VERSION 5.7 ;
  NOWIREEXTENSIONATPIN ON ;
  DIVIDERCHAR "/" ;
  BUSBITCHARS "[]" ;
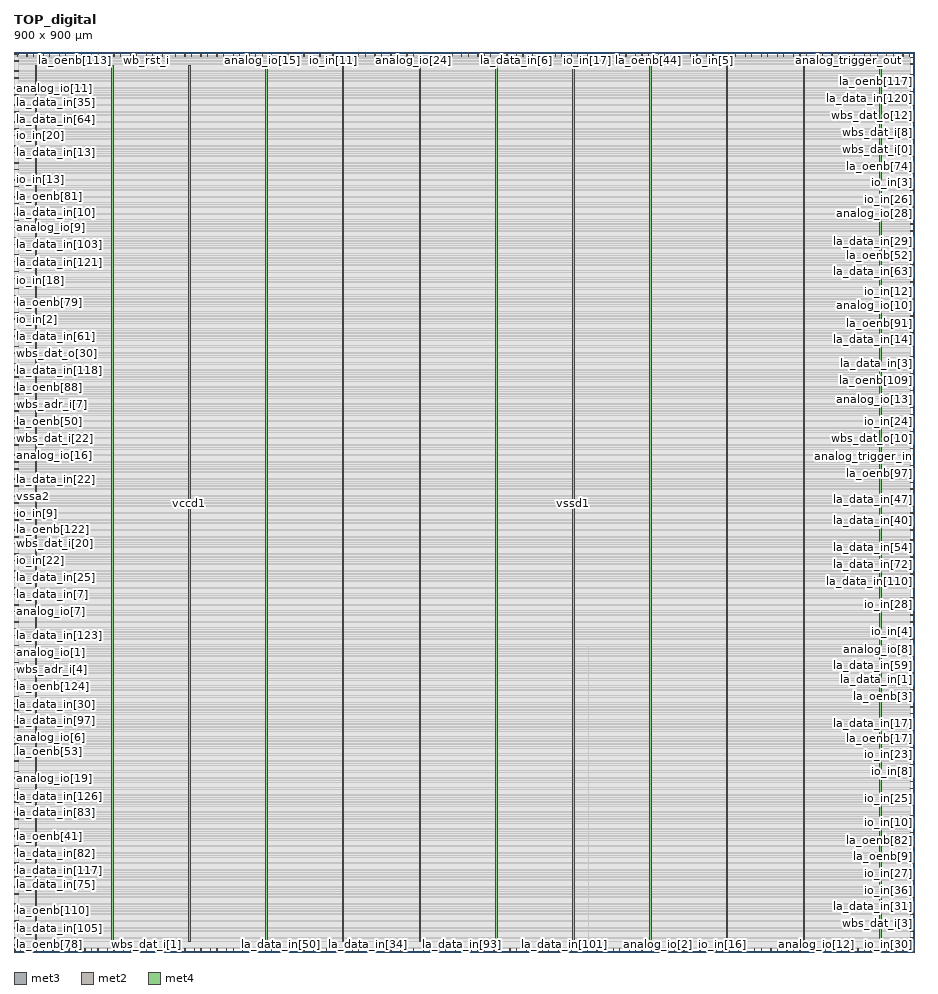
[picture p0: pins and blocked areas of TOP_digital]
MACRO TOP_digital
  CLASS BLOCK ;
  FOREIGN TOP_digital ;
  ORIGIN 0.000 0.000 ;
  SIZE 900.000 BY 900.000 ;
  PIN analog_io[0]
    DIRECTION INOUT ;
    USE SIGNAL ;
    PORT
      LAYER met3 ;
        RECT 0.000 639.240 4.000 639.840 ;
    END
  END analog_io[0]
  PIN analog_io[10]
    DIRECTION INOUT ;
    USE SIGNAL ;
    PORT
      LAYER met3 ;
        RECT 896.000 646.040 900.000 646.640 ;
    END
  END analog_io[10]
  PIN analog_io[11]
    DIRECTION INOUT ;
    USE SIGNAL ;
    PORT
      LAYER met3 ;
        RECT 0.000 863.640 4.000 864.240 ;
    END
  END analog_io[11]
  PIN analog_io[12]
    DIRECTION INOUT ;
    USE SIGNAL ;
    PORT
      LAYER met2 ;
        RECT 801.870 0.000 802.150 4.000 ;
    END
  END analog_io[12]
  PIN analog_io[13]
    DIRECTION INOUT ;
    USE SIGNAL ;
    PORT
      LAYER met3 ;
        RECT 896.000 544.040 900.000 544.640 ;
    END
  END analog_io[13]
  PIN analog_io[14]
    DIRECTION INOUT ;
    USE SIGNAL ;
    PORT
      LAYER met3 ;
        RECT 896.000 877.240 900.000 877.840 ;
    END
  END analog_io[14]
  PIN analog_io[15]
    DIRECTION INOUT ;
    USE SIGNAL ;
    PORT
      LAYER met2 ;
        RECT 248.030 896.000 248.310 900.000 ;
    END
  END analog_io[15]
  PIN analog_io[16]
    DIRECTION INOUT ;
    USE SIGNAL ;
    PORT
      LAYER met3 ;
        RECT 0.000 496.440 4.000 497.040 ;
    END
  END analog_io[16]
  PIN analog_io[17]
    DIRECTION INOUT ;
    USE SIGNAL ;
    PORT
      LAYER met2 ;
        RECT 106.350 896.000 106.630 900.000 ;
    END
  END analog_io[17]
  PIN analog_io[18]
    DIRECTION INOUT ;
    USE SIGNAL ;
    PORT
      LAYER met2 ;
        RECT 67.710 896.000 67.990 900.000 ;
    END
  END analog_io[18]
  PIN analog_io[19]
    DIRECTION INOUT ;
    USE SIGNAL ;
    PORT
      LAYER met3 ;
        RECT 0.000 173.440 4.000 174.040 ;
    END
  END analog_io[19]
  PIN analog_io[1]
    DIRECTION INOUT ;
    USE SIGNAL ;
    PORT
      LAYER met3 ;
        RECT 0.000 299.240 4.000 299.840 ;
    END
  END analog_io[1]
  PIN analog_io[20]
    DIRECTION INOUT ;
    USE SIGNAL ;
    PORT
      LAYER met3 ;
        RECT 0.000 363.840 4.000 364.440 ;
    END
  END analog_io[20]
  PIN analog_io[21]
    DIRECTION INOUT ;
    USE SIGNAL ;
    PORT
      LAYER met2 ;
        RECT 621.550 896.000 621.830 900.000 ;
    END
  END analog_io[21]
  PIN analog_io[22]
    DIRECTION INOUT ;
    USE SIGNAL ;
    PORT
      LAYER met2 ;
        RECT 77.370 896.000 77.650 900.000 ;
    END
  END analog_io[22]
  PIN analog_io[23]
    DIRECTION INOUT ;
    USE SIGNAL ;
    PORT
      LAYER met2 ;
        RECT 785.770 0.000 786.050 4.000 ;
    END
  END analog_io[23]
  PIN analog_io[24]
    DIRECTION INOUT ;
    USE SIGNAL ;
    PORT
      LAYER met2 ;
        RECT 399.370 896.000 399.650 900.000 ;
    END
  END analog_io[24]
  PIN analog_io[25]
    DIRECTION INOUT ;
    USE SIGNAL ;
    PORT
      LAYER met3 ;
        RECT 0.000 880.640 4.000 881.240 ;
    END
  END analog_io[25]
  PIN analog_io[26]
    DIRECTION INOUT ;
    USE SIGNAL ;
    PORT
      LAYER met2 ;
        RECT 714.930 896.000 715.210 900.000 ;
    END
  END analog_io[26]
  PIN analog_io[27]
    DIRECTION INOUT ;
    USE SIGNAL ;
    PORT
      LAYER met3 ;
        RECT 0.000 47.640 4.000 48.240 ;
    END
  END analog_io[27]
  PIN analog_io[28]
    DIRECTION INOUT ;
    USE SIGNAL ;
    PORT
      LAYER met3 ;
        RECT 896.000 737.840 900.000 738.440 ;
    END
  END analog_io[28]
  PIN analog_io[2]
    DIRECTION INOUT ;
    USE SIGNAL ;
    PORT
      LAYER met2 ;
        RECT 644.090 0.000 644.370 4.000 ;
    END
  END analog_io[2]
  PIN analog_io[3]
    DIRECTION INOUT ;
    USE SIGNAL ;
    PORT
      LAYER met2 ;
        RECT 431.570 0.000 431.850 4.000 ;
    END
  END analog_io[3]
  PIN analog_io[4]
    DIRECTION INOUT ;
    USE SIGNAL ;
    PORT
      LAYER met2 ;
        RECT 476.650 896.000 476.930 900.000 ;
    END
  END analog_io[4]
  PIN analog_io[5]
    DIRECTION INOUT ;
    USE SIGNAL ;
    PORT
      LAYER met2 ;
        RECT 99.910 0.000 100.190 4.000 ;
    END
  END analog_io[5]
  PIN analog_io[6]
    DIRECTION INOUT ;
    USE SIGNAL ;
    PORT
      LAYER met3 ;
        RECT 0.000 214.240 4.000 214.840 ;
    END
  END analog_io[6]
  PIN analog_io[7]
    DIRECTION INOUT ;
    USE SIGNAL ;
    PORT
      LAYER met3 ;
        RECT 0.000 340.040 4.000 340.640 ;
    END
  END analog_io[7]
  PIN analog_io[8]
    DIRECTION INOUT ;
    USE SIGNAL ;
    PORT
      LAYER met3 ;
        RECT 896.000 302.640 900.000 303.240 ;
    END
  END analog_io[8]
  PIN analog_io[9]
    DIRECTION INOUT ;
    USE SIGNAL ;
    PORT
      LAYER met3 ;
        RECT 0.000 724.240 4.000 724.840 ;
    END
  END analog_io[9]
  PIN analog_trigger_in
    DIRECTION INOUT ;
    USE SIGNAL ;
    PORT
      LAYER met3 ;
        RECT 896.000 503.240 900.000 503.840 ;
    END
  END analog_trigger_in
  PIN analog_trigger_out
    DIRECTION INOUT ;
    USE SIGNAL ;
    PORT
      LAYER met2 ;
        RECT 834.070 896.000 834.350 900.000 ;
    END
  END analog_trigger_out
  PIN io_in[0]
    DIRECTION INPUT ;
    USE SIGNAL ;
    PORT
      LAYER met3 ;
        RECT 896.000 105.440 900.000 106.040 ;
    END
  END io_in[0]
  PIN io_in[10]
    DIRECTION INPUT ;
    USE SIGNAL ;
    PORT
      LAYER met3 ;
        RECT 896.000 129.240 900.000 129.840 ;
    END
  END io_in[10]
  PIN io_in[11]
    DIRECTION INPUT ;
    USE SIGNAL ;
    PORT
      LAYER met2 ;
        RECT 318.870 896.000 319.150 900.000 ;
    END
  END io_in[11]
  PIN io_in[12]
    DIRECTION INPUT ;
    USE SIGNAL ;
    PORT
      LAYER met3 ;
        RECT 896.000 652.840 900.000 653.440 ;
    END
  END io_in[12]
  PIN io_in[13]
    DIRECTION INPUT ;
    USE SIGNAL ;
    PORT
      LAYER met3 ;
        RECT 0.000 771.840 4.000 772.440 ;
    END
  END io_in[13]
  PIN io_in[14]
    DIRECTION INPUT ;
    USE SIGNAL ;
    PORT
      LAYER met2 ;
        RECT 772.890 0.000 773.170 4.000 ;
    END
  END io_in[14]
  PIN io_in[15]
    DIRECTION INPUT ;
    USE SIGNAL ;
    PORT
      LAYER met3 ;
        RECT 0.000 105.440 4.000 106.040 ;
    END
  END io_in[15]
  PIN io_in[16]
    DIRECTION INPUT ;
    USE SIGNAL ;
    PORT
      LAYER met2 ;
        RECT 708.490 0.000 708.770 4.000 ;
    END
  END io_in[16]
  PIN io_in[17]
    DIRECTION INPUT ;
    USE SIGNAL ;
    PORT
      LAYER met2 ;
        RECT 573.250 896.000 573.530 900.000 ;
    END
  END io_in[17]
  PIN io_in[18]
    DIRECTION INPUT ;
    USE SIGNAL ;
    PORT
      LAYER met3 ;
        RECT 0.000 663.040 4.000 663.640 ;
    END
  END io_in[18]
  PIN io_in[19]
    DIRECTION INPUT ;
    USE SIGNAL ;
    PORT
      LAYER met2 ;
        RECT 817.970 0.000 818.250 4.000 ;
    END
  END io_in[19]
  PIN io_in[1]
    DIRECTION INPUT ;
    USE SIGNAL ;
    PORT
      LAYER met2 ;
        RECT 22.630 0.000 22.910 4.000 ;
    END
  END io_in[1]
  PIN io_in[20]
    DIRECTION INPUT ;
    USE SIGNAL ;
    PORT
      LAYER met3 ;
        RECT 0.000 816.040 4.000 816.640 ;
    END
  END io_in[20]
  PIN io_in[21]
    DIRECTION INPUT ;
    USE SIGNAL ;
    PORT
      LAYER met2 ;
        RECT 660.190 0.000 660.470 4.000 ;
    END
  END io_in[21]
  PIN io_in[22]
    DIRECTION INPUT ;
    USE SIGNAL ;
    PORT
      LAYER met3 ;
        RECT 0.000 391.040 4.000 391.640 ;
    END
  END io_in[22]
  PIN io_in[23]
    DIRECTION INPUT ;
    USE SIGNAL ;
    PORT
      LAYER met3 ;
        RECT 896.000 197.240 900.000 197.840 ;
    END
  END io_in[23]
  PIN io_in[24]
    DIRECTION INPUT ;
    USE SIGNAL ;
    PORT
      LAYER met3 ;
        RECT 896.000 530.440 900.000 531.040 ;
    END
  END io_in[24]
  PIN io_in[25]
    DIRECTION INPUT ;
    USE SIGNAL ;
    PORT
      LAYER met3 ;
        RECT 896.000 153.040 900.000 153.640 ;
    END
  END io_in[25]
  PIN io_in[26]
    DIRECTION INPUT ;
    USE SIGNAL ;
    PORT
      LAYER met3 ;
        RECT 896.000 744.640 900.000 745.240 ;
    END
  END io_in[26]
  PIN io_in[27]
    DIRECTION INPUT ;
    USE SIGNAL ;
    PORT
      LAYER met3 ;
        RECT 896.000 78.240 900.000 78.840 ;
    END
  END io_in[27]
  PIN io_in[28]
    DIRECTION INPUT ;
    USE SIGNAL ;
    PORT
      LAYER met3 ;
        RECT 896.000 346.840 900.000 347.440 ;
    END
  END io_in[28]
  PIN io_in[29]
    DIRECTION INPUT ;
    USE SIGNAL ;
    PORT
      LAYER met2 ;
        RECT 122.450 896.000 122.730 900.000 ;
    END
  END io_in[29]
  PIN io_in[2]
    DIRECTION INPUT ;
    USE SIGNAL ;
    PORT
      LAYER met3 ;
        RECT 0.000 632.440 4.000 633.040 ;
    END
  END io_in[2]
  PIN io_in[30]
    DIRECTION INPUT ;
    USE SIGNAL ;
    PORT
      LAYER met2 ;
        RECT 898.470 0.000 898.750 4.000 ;
    END
  END io_in[30]
  PIN io_in[31]
    DIRECTION INPUT ;
    USE SIGNAL ;
    PORT
      LAYER met2 ;
        RECT 116.010 0.000 116.290 4.000 ;
    END
  END io_in[31]
  PIN io_in[32]
    DIRECTION INPUT ;
    USE SIGNAL ;
    PORT
      LAYER met2 ;
        RECT 29.070 896.000 29.350 900.000 ;
    END
  END io_in[32]
  PIN io_in[33]
    DIRECTION INPUT ;
    USE SIGNAL ;
    PORT
      LAYER met3 ;
        RECT 896.000 13.640 900.000 14.240 ;
    END
  END io_in[33]
  PIN io_in[34]
    DIRECTION INPUT ;
    USE SIGNAL ;
    PORT
      LAYER met2 ;
        RECT 289.890 0.000 290.170 4.000 ;
    END
  END io_in[34]
  PIN io_in[35]
    DIRECTION INPUT ;
    USE SIGNAL ;
    PORT
      LAYER met2 ;
        RECT 856.610 896.000 856.890 900.000 ;
    END
  END io_in[35]
  PIN io_in[36]
    DIRECTION INPUT ;
    USE SIGNAL ;
    PORT
      LAYER met3 ;
        RECT 896.000 61.240 900.000 61.840 ;
    END
  END io_in[36]
  PIN io_in[37]
    DIRECTION INPUT ;
    USE SIGNAL ;
    PORT
      LAYER met3 ;
        RECT 0.000 329.840 4.000 330.440 ;
    END
  END io_in[37]
  PIN io_in[3]
    DIRECTION INPUT ;
    USE SIGNAL ;
    PORT
      LAYER met3 ;
        RECT 896.000 761.640 900.000 762.240 ;
    END
  END io_in[3]
  PIN io_in[4]
    DIRECTION INPUT ;
    USE SIGNAL ;
    PORT
      LAYER met3 ;
        RECT 896.000 312.840 900.000 313.440 ;
    END
  END io_in[4]
  PIN io_in[5]
    DIRECTION INPUT ;
    USE SIGNAL ;
    PORT
      LAYER met2 ;
        RECT 698.830 896.000 699.110 900.000 ;
    END
  END io_in[5]
  PIN io_in[6]
    DIRECTION INPUT ;
    USE SIGNAL ;
    PORT
      LAYER met2 ;
        RECT 888.810 896.000 889.090 900.000 ;
    END
  END io_in[6]
  PIN io_in[7]
    DIRECTION INPUT ;
    USE SIGNAL ;
    PORT
      LAYER met2 ;
        RECT 740.690 0.000 740.970 4.000 ;
    END
  END io_in[7]
  PIN io_in[8]
    DIRECTION INPUT ;
    USE SIGNAL ;
    PORT
      LAYER met3 ;
        RECT 896.000 180.240 900.000 180.840 ;
    END
  END io_in[8]
  PIN io_in[9]
    DIRECTION INPUT ;
    USE SIGNAL ;
    PORT
      LAYER met3 ;
        RECT 0.000 438.640 4.000 439.240 ;
    END
  END io_in[9]
  PIN la_data_in[0]
    DIRECTION INPUT ;
    USE SIGNAL ;
    ANTENNAGATEAREA 0.495000 ;
    PORT
      LAYER met3 ;
        RECT 0.000 132.640 4.000 133.240 ;
    END
  END la_data_in[0]
  PIN la_data_in[100]
    DIRECTION INPUT ;
    USE SIGNAL ;
    PORT
      LAYER met2 ;
        RECT 328.530 896.000 328.810 900.000 ;
    END
  END la_data_in[100]
  PIN la_data_in[101]
    DIRECTION INPUT ;
    USE SIGNAL ;
    PORT
      LAYER met2 ;
        RECT 550.710 0.000 550.990 4.000 ;
    END
  END la_data_in[101]
  PIN la_data_in[102]
    DIRECTION INPUT ;
    USE SIGNAL ;
    PORT
      LAYER met2 ;
        RECT 312.430 896.000 312.710 900.000 ;
    END
  END la_data_in[102]
  PIN la_data_in[103]
    DIRECTION INPUT ;
    USE SIGNAL ;
    PORT
      LAYER met3 ;
        RECT 0.000 707.240 4.000 707.840 ;
    END
  END la_data_in[103]
  PIN la_data_in[104]
    DIRECTION INPUT ;
    USE SIGNAL ;
    PORT
      LAYER met2 ;
        RECT 415.470 896.000 415.750 900.000 ;
    END
  END la_data_in[104]
  PIN la_data_in[105]
    DIRECTION INPUT ;
    USE SIGNAL ;
    PORT
      LAYER met3 ;
        RECT 0.000 30.640 4.000 31.240 ;
    END
  END la_data_in[105]
  PIN la_data_in[106]
    DIRECTION INPUT ;
    USE SIGNAL ;
    PORT
      LAYER met2 ;
        RECT 148.210 0.000 148.490 4.000 ;
    END
  END la_data_in[106]
  PIN la_data_in[107]
    DIRECTION INPUT ;
    USE SIGNAL ;
    PORT
      LAYER met2 ;
        RECT 425.130 0.000 425.410 4.000 ;
    END
  END la_data_in[107]
  PIN la_data_in[108]
    DIRECTION INPUT ;
    USE SIGNAL ;
    PORT
      LAYER met2 ;
        RECT 544.270 0.000 544.550 4.000 ;
    END
  END la_data_in[108]
  PIN la_data_in[109]
    DIRECTION INPUT ;
    USE SIGNAL ;
    PORT
      LAYER met3 ;
        RECT 896.000 520.240 900.000 520.840 ;
    END
  END la_data_in[109]
  PIN la_data_in[10]
    DIRECTION INPUT ;
    USE SIGNAL ;
    PORT
      LAYER met3 ;
        RECT 0.000 731.040 4.000 731.640 ;
    END
  END la_data_in[10]
  PIN la_data_in[110]
    DIRECTION INPUT ;
    USE SIGNAL ;
    PORT
      LAYER met3 ;
        RECT 896.000 370.640 900.000 371.240 ;
    END
  END la_data_in[110]
  PIN la_data_in[111]
    DIRECTION INPUT ;
    USE SIGNAL ;
    PORT
      LAYER met3 ;
        RECT 896.000 812.640 900.000 813.240 ;
    END
  END la_data_in[111]
  PIN la_data_in[112]
    DIRECTION INPUT ;
    USE SIGNAL ;
    PORT
      LAYER met3 ;
        RECT 896.000 846.640 900.000 847.240 ;
    END
  END la_data_in[112]
  PIN la_data_in[113]
    DIRECTION INPUT ;
    USE SIGNAL ;
    PORT
      LAYER met2 ;
        RECT 219.050 0.000 219.330 4.000 ;
    END
  END la_data_in[113]
  PIN la_data_in[114]
    DIRECTION INPUT ;
    USE SIGNAL ;
    PORT
      LAYER met3 ;
        RECT 896.000 71.440 900.000 72.040 ;
    END
  END la_data_in[114]
  PIN la_data_in[115]
    DIRECTION INPUT ;
    USE SIGNAL ;
    PORT
      LAYER met2 ;
        RECT 83.810 0.000 84.090 4.000 ;
    END
  END la_data_in[115]
  PIN la_data_in[116]
    DIRECTION INPUT ;
    USE SIGNAL ;
    PORT
      LAYER met2 ;
        RECT 573.250 0.000 573.530 4.000 ;
    END
  END la_data_in[116]
  PIN la_data_in[117]
    DIRECTION INPUT ;
    USE SIGNAL ;
    PORT
      LAYER met3 ;
        RECT 0.000 81.640 4.000 82.240 ;
    END
  END la_data_in[117]
  PIN la_data_in[118]
    DIRECTION INPUT ;
    USE SIGNAL ;
    PORT
      LAYER met3 ;
        RECT 0.000 581.440 4.000 582.040 ;
    END
  END la_data_in[118]
  PIN la_data_in[119]
    DIRECTION INPUT ;
    USE SIGNAL ;
    PORT
      LAYER met2 ;
        RECT 405.810 896.000 406.090 900.000 ;
    END
  END la_data_in[119]
  PIN la_data_in[11]
    DIRECTION INPUT ;
    USE SIGNAL ;
    PORT
      LAYER met3 ;
        RECT 0.000 656.240 4.000 656.840 ;
    END
  END la_data_in[11]
  PIN la_data_in[120]
    DIRECTION INPUT ;
    USE SIGNAL ;
    PORT
      LAYER met3 ;
        RECT 896.000 853.440 900.000 854.040 ;
    END
  END la_data_in[120]
  PIN la_data_in[121]
    DIRECTION INPUT ;
    USE SIGNAL ;
    PORT
      LAYER met3 ;
        RECT 0.000 697.040 4.000 697.640 ;
    END
  END la_data_in[121]
  PIN la_data_in[122]
    DIRECTION INPUT ;
    USE SIGNAL ;
    PORT
      LAYER met2 ;
        RECT 125.670 0.000 125.950 4.000 ;
    END
  END la_data_in[122]
  PIN la_data_in[123]
    DIRECTION INPUT ;
    USE SIGNAL ;
    PORT
      LAYER met3 ;
        RECT 0.000 316.240 4.000 316.840 ;
    END
  END la_data_in[123]
  PIN la_data_in[124]
    DIRECTION INPUT ;
    USE SIGNAL ;
    PORT
      LAYER met3 ;
        RECT 0.000 557.640 4.000 558.240 ;
    END
  END la_data_in[124]
  PIN la_data_in[125]
    DIRECTION INPUT ;
    USE SIGNAL ;
    PORT
      LAYER met2 ;
        RECT 827.630 0.000 827.910 4.000 ;
    END
  END la_data_in[125]
  PIN la_data_in[126]
    DIRECTION INPUT ;
    USE SIGNAL ;
    PORT
      LAYER met3 ;
        RECT 0.000 163.240 4.000 163.840 ;
    END
  END la_data_in[126]
  PIN la_data_in[127]
    DIRECTION INPUT ;
    USE SIGNAL ;
    PORT
      LAYER met2 ;
        RECT 518.510 896.000 518.790 900.000 ;
    END
  END la_data_in[127]
  PIN la_data_in[12]
    DIRECTION INPUT ;
    USE SIGNAL ;
    PORT
      LAYER met2 ;
        RECT 219.050 896.000 219.330 900.000 ;
    END
  END la_data_in[12]
  PIN la_data_in[13]
    DIRECTION INPUT ;
    USE SIGNAL ;
    PORT
      LAYER met3 ;
        RECT 0.000 799.040 4.000 799.640 ;
    END
  END la_data_in[13]
  PIN la_data_in[14]
    DIRECTION INPUT ;
    USE SIGNAL ;
    PORT
      LAYER met3 ;
        RECT 896.000 612.040 900.000 612.640 ;
    END
  END la_data_in[14]
  PIN la_data_in[15]
    DIRECTION INPUT ;
    USE SIGNAL ;
    PORT
      LAYER met2 ;
        RECT 792.210 896.000 792.490 900.000 ;
    END
  END la_data_in[15]
  PIN la_data_in[16]
    DIRECTION INPUT ;
    USE SIGNAL ;
    PORT
      LAYER met2 ;
        RECT 3.310 896.000 3.590 900.000 ;
    END
  END la_data_in[16]
  PIN la_data_in[17]
    DIRECTION INPUT ;
    USE SIGNAL ;
    PORT
      LAYER met3 ;
        RECT 896.000 227.840 900.000 228.440 ;
    END
  END la_data_in[17]
  PIN la_data_in[18]
    DIRECTION INPUT ;
    USE SIGNAL ;
    PORT
      LAYER met3 ;
        RECT 0.000 323.040 4.000 323.640 ;
    END
  END la_data_in[18]
  PIN la_data_in[19]
    DIRECTION INPUT ;
    USE SIGNAL ;
    PORT
      LAYER met2 ;
        RECT 421.910 896.000 422.190 900.000 ;
    END
  END la_data_in[19]
  PIN la_data_in[1]
    DIRECTION INPUT ;
    USE SIGNAL ;
    PORT
      LAYER met3 ;
        RECT 896.000 272.040 900.000 272.640 ;
    END
  END la_data_in[1]
  PIN la_data_in[20]
    DIRECTION INPUT ;
    USE SIGNAL ;
    PORT
      LAYER met2 ;
        RECT 177.190 896.000 177.470 900.000 ;
    END
  END la_data_in[20]
  PIN la_data_in[21]
    DIRECTION INPUT ;
    USE SIGNAL ;
    PORT
      LAYER met3 ;
        RECT 896.000 210.840 900.000 211.440 ;
    END
  END la_data_in[21]
  PIN la_data_in[22]
    DIRECTION INPUT ;
    USE SIGNAL ;
    PORT
      LAYER met3 ;
        RECT 0.000 472.640 4.000 473.240 ;
    END
  END la_data_in[22]
  PIN la_data_in[23]
    DIRECTION INPUT ;
    USE SIGNAL ;
    PORT
      LAYER met3 ;
        RECT 0.000 622.240 4.000 622.840 ;
    END
  END la_data_in[23]
  PIN la_data_in[24]
    DIRECTION INPUT ;
    USE SIGNAL ;
    PORT
      LAYER met2 ;
        RECT 872.710 896.000 872.990 900.000 ;
    END
  END la_data_in[24]
  PIN la_data_in[25]
    DIRECTION INPUT ;
    USE SIGNAL ;
    PORT
      LAYER met3 ;
        RECT 0.000 374.040 4.000 374.640 ;
    END
  END la_data_in[25]
  PIN la_data_in[26]
    DIRECTION INPUT ;
    USE SIGNAL ;
    PORT
      LAYER met2 ;
        RECT 508.850 896.000 509.130 900.000 ;
    END
  END la_data_in[26]
  PIN la_data_in[27]
    DIRECTION INPUT ;
    USE SIGNAL ;
    PORT
      LAYER met3 ;
        RECT 0.000 122.440 4.000 123.040 ;
    END
  END la_data_in[27]
  PIN la_data_in[28]
    DIRECTION INPUT ;
    USE SIGNAL ;
    PORT
      LAYER met3 ;
        RECT 0.000 506.640 4.000 507.240 ;
    END
  END la_data_in[28]
  PIN la_data_in[29]
    DIRECTION INPUT ;
    USE SIGNAL ;
    PORT
      LAYER met3 ;
        RECT 896.000 710.640 900.000 711.240 ;
    END
  END la_data_in[29]
  PIN la_data_in[2]
    DIRECTION INPUT ;
    USE SIGNAL ;
    PORT
      LAYER met3 ;
        RECT 0.000 805.840 4.000 806.440 ;
    END
  END la_data_in[2]
  PIN la_data_in[30]
    DIRECTION INPUT ;
    USE SIGNAL ;
    PORT
      LAYER met3 ;
        RECT 0.000 255.040 4.000 255.640 ;
    END
  END la_data_in[30]
  PIN la_data_in[31]
    DIRECTION INPUT ;
    USE SIGNAL ;
    PORT
      LAYER met3 ;
        RECT 896.000 37.440 900.000 38.040 ;
    END
  END la_data_in[31]
  PIN la_data_in[32]
    DIRECTION INPUT ;
    USE SIGNAL ;
    PORT
      LAYER met2 ;
        RECT 90.250 896.000 90.530 900.000 ;
    END
  END la_data_in[32]
  PIN la_data_in[33]
    DIRECTION INPUT ;
    USE SIGNAL ;
    PORT
      LAYER met2 ;
        RECT 808.310 896.000 808.590 900.000 ;
    END
  END la_data_in[33]
  PIN la_data_in[34]
    DIRECTION INPUT ;
    USE SIGNAL ;
    PORT
      LAYER met2 ;
        RECT 354.290 0.000 354.570 4.000 ;
    END
  END la_data_in[34]
  PIN la_data_in[35]
    DIRECTION INPUT ;
    USE SIGNAL ;
    PORT
      LAYER met3 ;
        RECT 0.000 856.840 4.000 857.440 ;
    END
  END la_data_in[35]
  PIN la_data_in[36]
    DIRECTION INPUT ;
    USE SIGNAL ;
    PORT
      LAYER met2 ;
        RECT 447.670 896.000 447.950 900.000 ;
    END
  END la_data_in[36]
  PIN la_data_in[37]
    DIRECTION INPUT ;
    USE SIGNAL ;
    PORT
      LAYER met3 ;
        RECT 896.000 112.240 900.000 112.840 ;
    END
  END la_data_in[37]
  PIN la_data_in[38]
    DIRECTION INPUT ;
    USE SIGNAL ;
    PORT
      LAYER met2 ;
        RECT 863.050 896.000 863.330 900.000 ;
    END
  END la_data_in[38]
  PIN la_data_in[39]
    DIRECTION INPUT ;
    USE SIGNAL ;
    PORT
      LAYER met2 ;
        RECT 676.290 896.000 676.570 900.000 ;
    END
  END la_data_in[39]
  PIN la_data_in[3]
    DIRECTION INPUT ;
    USE SIGNAL ;
    PORT
      LAYER met3 ;
        RECT 896.000 588.240 900.000 588.840 ;
    END
  END la_data_in[3]
  PIN la_data_in[40]
    DIRECTION INPUT ;
    USE SIGNAL ;
    PORT
      LAYER met3 ;
        RECT 896.000 438.640 900.000 439.240 ;
    END
  END la_data_in[40]
  PIN la_data_in[41]
    DIRECTION INPUT ;
    USE SIGNAL ;
    PORT
      LAYER met2 ;
        RECT 524.950 896.000 525.230 900.000 ;
    END
  END la_data_in[41]
  PIN la_data_in[42]
    DIRECTION INPUT ;
    USE SIGNAL ;
    PORT
      LAYER met2 ;
        RECT 621.550 0.000 621.830 4.000 ;
    END
  END la_data_in[42]
  PIN la_data_in[43]
    DIRECTION INPUT ;
    USE SIGNAL ;
    PORT
      LAYER met3 ;
        RECT 0.000 23.840 4.000 24.440 ;
    END
  END la_data_in[43]
  PIN la_data_in[44]
    DIRECTION INPUT ;
    USE SIGNAL ;
    PORT
      LAYER met3 ;
        RECT 0.000 13.640 4.000 14.240 ;
    END
  END la_data_in[44]
  PIN la_data_in[45]
    DIRECTION INPUT ;
    USE SIGNAL ;
    PORT
      LAYER met2 ;
        RECT 351.070 896.000 351.350 900.000 ;
    END
  END la_data_in[45]
  PIN la_data_in[46]
    DIRECTION INPUT ;
    USE SIGNAL ;
    PORT
      LAYER met3 ;
        RECT 0.000 782.040 4.000 782.640 ;
    END
  END la_data_in[46]
  PIN la_data_in[47]
    DIRECTION INPUT ;
    USE SIGNAL ;
    PORT
      LAYER met3 ;
        RECT 896.000 452.240 900.000 452.840 ;
    END
  END la_data_in[47]
  PIN la_data_in[48]
    DIRECTION INPUT ;
    USE SIGNAL ;
    PORT
      LAYER met2 ;
        RECT 534.610 896.000 534.890 900.000 ;
    END
  END la_data_in[48]
  PIN la_data_in[49]
    DIRECTION INPUT ;
    USE SIGNAL ;
    PORT
      LAYER met2 ;
        RECT 154.650 0.000 154.930 4.000 ;
    END
  END la_data_in[49]
  PIN la_data_in[4]
    DIRECTION INPUT ;
    USE SIGNAL ;
    PORT
      LAYER met2 ;
        RECT 756.790 0.000 757.070 4.000 ;
    END
  END la_data_in[4]
  PIN la_data_in[50]
    DIRECTION INPUT ;
    USE SIGNAL ;
    PORT
      LAYER met2 ;
        RECT 267.350 0.000 267.630 4.000 ;
    END
  END la_data_in[50]
  PIN la_data_in[51]
    DIRECTION INPUT ;
    USE SIGNAL ;
    PORT
      LAYER met2 ;
        RECT 714.930 0.000 715.210 4.000 ;
    END
  END la_data_in[51]
  PIN la_data_in[52]
    DIRECTION INPUT ;
    USE SIGNAL ;
    PORT
      LAYER met3 ;
        RECT 896.000 136.040 900.000 136.640 ;
    END
  END la_data_in[52]
  PIN la_data_in[53]
    DIRECTION INPUT ;
    USE SIGNAL ;
    PORT
      LAYER met2 ;
        RECT 392.930 0.000 393.210 4.000 ;
    END
  END la_data_in[53]
  PIN la_data_in[54]
    DIRECTION INPUT ;
    USE SIGNAL ;
    PORT
      LAYER met3 ;
        RECT 896.000 404.640 900.000 405.240 ;
    END
  END la_data_in[54]
  PIN la_data_in[55]
    DIRECTION INPUT ;
    USE SIGNAL ;
    PORT
      LAYER met2 ;
        RECT 296.330 896.000 296.610 900.000 ;
    END
  END la_data_in[55]
  PIN la_data_in[56]
    DIRECTION INPUT ;
    USE SIGNAL ;
    PORT
      LAYER met2 ;
        RECT 12.970 896.000 13.250 900.000 ;
    END
  END la_data_in[56]
  PIN la_data_in[57]
    DIRECTION INPUT ;
    USE SIGNAL ;
    PORT
      LAYER met3 ;
        RECT 896.000 445.440 900.000 446.040 ;
    END
  END la_data_in[57]
  PIN la_data_in[58]
    DIRECTION INPUT ;
    USE SIGNAL ;
    PORT
      LAYER met2 ;
        RECT 763.230 896.000 763.510 900.000 ;
    END
  END la_data_in[58]
  PIN la_data_in[59]
    DIRECTION INPUT ;
    USE SIGNAL ;
    PORT
      LAYER met3 ;
        RECT 896.000 278.840 900.000 279.440 ;
    END
  END la_data_in[59]
  PIN la_data_in[5]
    DIRECTION INPUT ;
    USE SIGNAL ;
    PORT
      LAYER met2 ;
        RECT 731.030 0.000 731.310 4.000 ;
    END
  END la_data_in[5]
  PIN la_data_in[60]
    DIRECTION INPUT ;
    USE SIGNAL ;
    PORT
      LAYER met2 ;
        RECT 305.990 896.000 306.270 900.000 ;
    END
  END la_data_in[60]
  PIN la_data_in[61]
    DIRECTION INPUT ;
    USE SIGNAL ;
    PORT
      LAYER met3 ;
        RECT 0.000 615.440 4.000 616.040 ;
    END
  END la_data_in[61]
  PIN la_data_in[62]
    DIRECTION INPUT ;
    USE SIGNAL ;
    PORT
      LAYER met2 ;
        RECT 895.250 896.000 895.530 900.000 ;
    END
  END la_data_in[62]
  PIN la_data_in[63]
    DIRECTION INPUT ;
    USE SIGNAL ;
    PORT
      LAYER met3 ;
        RECT 896.000 680.040 900.000 680.640 ;
    END
  END la_data_in[63]
  PIN la_data_in[64]
    DIRECTION INPUT ;
    USE SIGNAL ;
    PORT
      LAYER met3 ;
        RECT 0.000 839.840 4.000 840.440 ;
    END
  END la_data_in[64]
  PIN la_data_in[65]
    DIRECTION INPUT ;
    USE SIGNAL ;
    PORT
      LAYER met2 ;
        RECT 370.390 0.000 370.670 4.000 ;
    END
  END la_data_in[65]
  PIN la_data_in[66]
    DIRECTION INPUT ;
    USE SIGNAL ;
    PORT
      LAYER met2 ;
        RECT 148.210 896.000 148.490 900.000 ;
    END
  END la_data_in[66]
  PIN la_data_in[67]
    DIRECTION INPUT ;
    USE SIGNAL ;
    PORT
      LAYER met2 ;
        RECT 627.990 0.000 628.270 4.000 ;
    END
  END la_data_in[67]
  PIN la_data_in[68]
    DIRECTION INPUT ;
    USE SIGNAL ;
    PORT
      LAYER met2 ;
        RECT 882.370 0.000 882.650 4.000 ;
    END
  END la_data_in[68]
  PIN la_data_in[69]
    DIRECTION INPUT ;
    USE SIGNAL ;
    PORT
      LAYER met2 ;
        RECT 322.090 0.000 322.370 4.000 ;
    END
  END la_data_in[69]
  PIN la_data_in[6]
    DIRECTION INPUT ;
    USE SIGNAL ;
    PORT
      LAYER met2 ;
        RECT 502.410 896.000 502.690 900.000 ;
    END
  END la_data_in[6]
  PIN la_data_in[70]
    DIRECTION INPUT ;
    USE SIGNAL ;
    PORT
      LAYER met3 ;
        RECT 896.000 363.840 900.000 364.440 ;
    END
  END la_data_in[70]
  PIN la_data_in[71]
    DIRECTION INPUT ;
    USE SIGNAL ;
    PORT
      LAYER met2 ;
        RECT 328.530 0.000 328.810 4.000 ;
    END
  END la_data_in[71]
  PIN la_data_in[72]
    DIRECTION INPUT ;
    USE SIGNAL ;
    PORT
      LAYER met3 ;
        RECT 896.000 394.440 900.000 395.040 ;
    END
  END la_data_in[72]
  PIN la_data_in[73]
    DIRECTION INPUT ;
    USE SIGNAL ;
    PORT
      LAYER met2 ;
        RECT 660.190 896.000 660.470 900.000 ;
    END
  END la_data_in[73]
  PIN la_data_in[74]
    DIRECTION INPUT ;
    USE SIGNAL ;
    PORT
      LAYER met3 ;
        RECT 0.000 149.640 4.000 150.240 ;
    END
  END la_data_in[74]
  PIN la_data_in[75]
    DIRECTION INPUT ;
    USE SIGNAL ;
    PORT
      LAYER met3 ;
        RECT 0.000 74.840 4.000 75.440 ;
    END
  END la_data_in[75]
  PIN la_data_in[76]
    DIRECTION INPUT ;
    USE SIGNAL ;
    PORT
      LAYER met3 ;
        RECT 0.000 890.840 4.000 891.440 ;
    END
  END la_data_in[76]
  PIN la_data_in[77]
    DIRECTION INPUT ;
    USE SIGNAL ;
    PORT
      LAYER met3 ;
        RECT 896.000 778.640 900.000 779.240 ;
    END
  END la_data_in[77]
  PIN la_data_in[78]
    DIRECTION INPUT ;
    USE SIGNAL ;
    PORT
      LAYER met3 ;
        RECT 896.000 771.840 900.000 772.440 ;
    END
  END la_data_in[78]
  PIN la_data_in[79]
    DIRECTION INPUT ;
    USE SIGNAL ;
    PORT
      LAYER met2 ;
        RECT 299.550 0.000 299.830 4.000 ;
    END
  END la_data_in[79]
  PIN la_data_in[7]
    DIRECTION INPUT ;
    USE SIGNAL ;
    PORT
      LAYER met3 ;
        RECT 0.000 357.040 4.000 357.640 ;
    END
  END la_data_in[7]
  PIN la_data_in[80]
    DIRECTION INPUT ;
    USE SIGNAL ;
    PORT
      LAYER met2 ;
        RECT 35.510 896.000 35.790 900.000 ;
    END
  END la_data_in[80]
  PIN la_data_in[81]
    DIRECTION INPUT ;
    USE SIGNAL ;
    PORT
      LAYER met3 ;
        RECT 0.000 6.840 4.000 7.440 ;
    END
  END la_data_in[81]
  PIN la_data_in[82]
    DIRECTION INPUT ;
    USE SIGNAL ;
    PORT
      LAYER met3 ;
        RECT 0.000 98.640 4.000 99.240 ;
    END
  END la_data_in[82]
  PIN la_data_in[83]
    DIRECTION INPUT ;
    USE SIGNAL ;
    PORT
      LAYER met3 ;
        RECT 0.000 139.440 4.000 140.040 ;
    END
  END la_data_in[83]
  PIN la_data_in[84]
    DIRECTION INPUT ;
    USE SIGNAL ;
    PORT
      LAYER met2 ;
        RECT 376.830 0.000 377.110 4.000 ;
    END
  END la_data_in[84]
  PIN la_data_in[85]
    DIRECTION INPUT ;
    USE SIGNAL ;
    PORT
      LAYER met2 ;
        RECT 579.690 896.000 579.970 900.000 ;
    END
  END la_data_in[85]
  PIN la_data_in[86]
    DIRECTION INPUT ;
    USE SIGNAL ;
    PORT
      LAYER met3 ;
        RECT 896.000 887.440 900.000 888.040 ;
    END
  END la_data_in[86]
  PIN la_data_in[87]
    DIRECTION INPUT ;
    USE SIGNAL ;
    PORT
      LAYER met2 ;
        RECT 312.430 0.000 312.710 4.000 ;
    END
  END la_data_in[87]
  PIN la_data_in[88]
    DIRECTION INPUT ;
    USE SIGNAL ;
    PORT
      LAYER met2 ;
        RECT 492.750 896.000 493.030 900.000 ;
    END
  END la_data_in[88]
  PIN la_data_in[89]
    DIRECTION INPUT ;
    USE SIGNAL ;
    PORT
      LAYER met2 ;
        RECT 605.450 0.000 605.730 4.000 ;
    END
  END la_data_in[89]
  PIN la_data_in[8]
    DIRECTION INPUT ;
    USE SIGNAL ;
    PORT
      LAYER met2 ;
        RECT 779.330 0.000 779.610 4.000 ;
    END
  END la_data_in[8]
  PIN la_data_in[90]
    DIRECTION INPUT ;
    USE SIGNAL ;
    PORT
      LAYER met2 ;
        RECT 344.630 896.000 344.910 900.000 ;
    END
  END la_data_in[90]
  PIN la_data_in[91]
    DIRECTION INPUT ;
    USE SIGNAL ;
    PORT
      LAYER met2 ;
        RECT 235.150 0.000 235.430 4.000 ;
    END
  END la_data_in[91]
  PIN la_data_in[92]
    DIRECTION INPUT ;
    USE SIGNAL ;
    PORT
      LAYER met2 ;
        RECT 289.890 896.000 290.170 900.000 ;
    END
  END la_data_in[92]
  PIN la_data_in[93]
    DIRECTION INPUT ;
    USE SIGNAL ;
    PORT
      LAYER met2 ;
        RECT 447.670 0.000 447.950 4.000 ;
    END
  END la_data_in[93]
  PIN la_data_in[94]
    DIRECTION INPUT ;
    USE SIGNAL ;
    PORT
      LAYER met3 ;
        RECT 896.000 411.440 900.000 412.040 ;
    END
  END la_data_in[94]
  PIN la_data_in[95]
    DIRECTION INPUT ;
    USE SIGNAL ;
    PORT
      LAYER met3 ;
        RECT 0.000 88.440 4.000 89.040 ;
    END
  END la_data_in[95]
  PIN la_data_in[96]
    DIRECTION INPUT ;
    USE SIGNAL ;
    PORT
      LAYER met3 ;
        RECT 896.000 353.640 900.000 354.240 ;
    END
  END la_data_in[96]
  PIN la_data_in[97]
    DIRECTION INPUT ;
    USE SIGNAL ;
    PORT
      LAYER met3 ;
        RECT 0.000 231.240 4.000 231.840 ;
    END
  END la_data_in[97]
  PIN la_data_in[98]
    DIRECTION INPUT ;
    USE SIGNAL ;
    PORT
      LAYER met2 ;
        RECT 653.750 0.000 654.030 4.000 ;
    END
  END la_data_in[98]
  PIN la_data_in[99]
    DIRECTION INPUT ;
    USE SIGNAL ;
    PORT
      LAYER met3 ;
        RECT 0.000 873.840 4.000 874.440 ;
    END
  END la_data_in[99]
  PIN la_data_in[9]
    DIRECTION INPUT ;
    USE SIGNAL ;
    PORT
      LAYER met2 ;
        RECT 193.290 896.000 193.570 900.000 ;
    END
  END la_data_in[9]
  PIN la_oenb[0]
    DIRECTION INPUT ;
    USE SIGNAL ;
    PORT
      LAYER met2 ;
        RECT 415.470 0.000 415.750 4.000 ;
    END
  END la_oenb[0]
  PIN la_oenb[100]
    DIRECTION INPUT ;
    USE SIGNAL ;
    PORT
      LAYER met2 ;
        RECT 367.170 896.000 367.450 900.000 ;
    END
  END la_oenb[100]
  PIN la_oenb[101]
    DIRECTION INPUT ;
    USE SIGNAL ;
    PORT
      LAYER met3 ;
        RECT 896.000 727.640 900.000 728.240 ;
    END
  END la_oenb[101]
  PIN la_oenb[102]
    DIRECTION INPUT ;
    USE SIGNAL ;
    PORT
      LAYER met2 ;
        RECT 495.970 0.000 496.250 4.000 ;
    END
  END la_oenb[102]
  PIN la_oenb[103]
    DIRECTION INPUT ;
    USE SIGNAL ;
    PORT
      LAYER met2 ;
        RECT 557.150 0.000 557.430 4.000 ;
    END
  END la_oenb[103]
  PIN la_oenb[104]
    DIRECTION INPUT ;
    USE SIGNAL ;
    PORT
      LAYER met3 ;
        RECT 0.000 482.840 4.000 483.440 ;
    END
  END la_oenb[104]
  PIN la_oenb[105]
    DIRECTION INPUT ;
    USE SIGNAL ;
    PORT
      LAYER met3 ;
        RECT 0.000 540.640 4.000 541.240 ;
    END
  END la_oenb[105]
  PIN la_oenb[106]
    DIRECTION INPUT ;
    USE SIGNAL ;
    PORT
      LAYER met2 ;
        RECT 785.770 896.000 786.050 900.000 ;
    END
  END la_oenb[106]
  PIN la_oenb[107]
    DIRECTION INPUT ;
    USE SIGNAL ;
    PORT
      LAYER met2 ;
        RECT 518.510 0.000 518.790 4.000 ;
    END
  END la_oenb[107]
  PIN la_oenb[108]
    DIRECTION INPUT ;
    USE SIGNAL ;
    PORT
      LAYER met2 ;
        RECT 872.710 0.000 872.990 4.000 ;
    END
  END la_oenb[108]
  PIN la_oenb[109]
    DIRECTION INPUT ;
    USE SIGNAL ;
    PORT
      LAYER met3 ;
        RECT 896.000 571.240 900.000 571.840 ;
    END
  END la_oenb[109]
  PIN la_oenb[10]
    DIRECTION INPUT ;
    USE SIGNAL ;
    PORT
      LAYER met3 ;
        RECT 896.000 595.040 900.000 595.640 ;
    END
  END la_oenb[10]
  PIN la_oenb[110]
    DIRECTION INPUT ;
    USE SIGNAL ;
    PORT
      LAYER met3 ;
        RECT 0.000 40.840 4.000 41.440 ;
    END
  END la_oenb[110]
  PIN la_oenb[111]
    DIRECTION INPUT ;
    USE SIGNAL ;
    PORT
      LAYER met2 ;
        RECT 305.990 0.000 306.270 4.000 ;
    END
  END la_oenb[111]
  PIN la_oenb[112]
    DIRECTION INPUT ;
    USE SIGNAL ;
    PORT
      LAYER met2 ;
        RECT 850.170 896.000 850.450 900.000 ;
    END
  END la_oenb[112]
  PIN la_oenb[113]
    DIRECTION INPUT ;
    USE SIGNAL ;
    PORT
      LAYER met2 ;
        RECT 61.270 896.000 61.550 900.000 ;
    END
  END la_oenb[113]
  PIN la_oenb[114]
    DIRECTION INPUT ;
    USE SIGNAL ;
    PORT
      LAYER met2 ;
        RECT 763.230 0.000 763.510 4.000 ;
    END
  END la_oenb[114]
  PIN la_oenb[115]
    DIRECTION INPUT ;
    USE SIGNAL ;
    PORT
      LAYER met2 ;
        RECT 611.890 896.000 612.170 900.000 ;
    END
  END la_oenb[115]
  PIN la_oenb[116]
    DIRECTION INPUT ;
    USE SIGNAL ;
    PORT
      LAYER met2 ;
        RECT 170.750 0.000 171.030 4.000 ;
    END
  END la_oenb[116]
  PIN la_oenb[117]
    DIRECTION INPUT ;
    USE SIGNAL ;
    PORT
      LAYER met3 ;
        RECT 896.000 870.440 900.000 871.040 ;
    END
  END la_oenb[117]
  PIN la_oenb[118]
    DIRECTION INPUT ;
    USE SIGNAL ;
    PORT
      LAYER met2 ;
        RECT 51.610 896.000 51.890 900.000 ;
    END
  END la_oenb[118]
  PIN la_oenb[119]
    DIRECTION INPUT ;
    USE SIGNAL ;
    PORT
      LAYER met2 ;
        RECT 431.570 896.000 431.850 900.000 ;
    END
  END la_oenb[119]
  PIN la_oenb[11]
    DIRECTION INPUT ;
    USE SIGNAL ;
    PORT
      LAYER met3 ;
        RECT 896.000 187.040 900.000 187.640 ;
    END
  END la_oenb[11]
  PIN la_oenb[120]
    DIRECTION INPUT ;
    USE SIGNAL ;
    PORT
      LAYER met3 ;
        RECT 896.000 754.840 900.000 755.440 ;
    END
  END la_oenb[120]
  PIN la_oenb[121]
    DIRECTION INPUT ;
    USE SIGNAL ;
    PORT
      LAYER met3 ;
        RECT 896.000 669.840 900.000 670.440 ;
    END
  END la_oenb[121]
  PIN la_oenb[122]
    DIRECTION INPUT ;
    USE SIGNAL ;
    PORT
      LAYER met3 ;
        RECT 0.000 414.840 4.000 415.440 ;
    END
  END la_oenb[122]
  PIN la_oenb[123]
    DIRECTION INPUT ;
    USE SIGNAL ;
    PORT
      LAYER met3 ;
        RECT 896.000 336.640 900.000 337.240 ;
    END
  END la_oenb[123]
  PIN la_oenb[124]
    DIRECTION INPUT ;
    USE SIGNAL ;
    PORT
      LAYER met3 ;
        RECT 0.000 265.240 4.000 265.840 ;
    END
  END la_oenb[124]
  PIN la_oenb[125]
    DIRECTION INPUT ;
    USE SIGNAL ;
    PORT
      LAYER met2 ;
        RECT 769.670 896.000 769.950 900.000 ;
    END
  END la_oenb[125]
  PIN la_oenb[126]
    DIRECTION INPUT ;
    USE SIGNAL ;
    PORT
      LAYER met2 ;
        RECT 463.770 896.000 464.050 900.000 ;
    END
  END la_oenb[126]
  PIN la_oenb[127]
    DIRECTION INPUT ;
    USE SIGNAL ;
    PORT
      LAYER met3 ;
        RECT 896.000 829.640 900.000 830.240 ;
    END
  END la_oenb[127]
  PIN la_oenb[12]
    DIRECTION INPUT ;
    USE SIGNAL ;
    PORT
      LAYER met2 ;
        RECT 409.030 0.000 409.310 4.000 ;
    END
  END la_oenb[12]
  PIN la_oenb[13]
    DIRECTION INPUT ;
    USE SIGNAL ;
    PORT
      LAYER met2 ;
        RECT 360.730 0.000 361.010 4.000 ;
    END
  END la_oenb[13]
  PIN la_oenb[14]
    DIRECTION INPUT ;
    USE SIGNAL ;
    PORT
      LAYER met3 ;
        RECT 896.000 496.440 900.000 497.040 ;
    END
  END la_oenb[14]
  PIN la_oenb[15]
    DIRECTION INPUT ;
    USE SIGNAL ;
    PORT
      LAYER met2 ;
        RECT 650.530 896.000 650.810 900.000 ;
    END
  END la_oenb[15]
  PIN la_oenb[16]
    DIRECTION INPUT ;
    USE SIGNAL ;
    PORT
      LAYER met2 ;
        RECT 747.130 0.000 747.410 4.000 ;
    END
  END la_oenb[16]
  PIN la_oenb[17]
    DIRECTION INPUT ;
    USE SIGNAL ;
    PORT
      LAYER met3 ;
        RECT 896.000 221.040 900.000 221.640 ;
    END
  END la_oenb[17]
  PIN la_oenb[18]
    DIRECTION INPUT ;
    USE SIGNAL ;
    PORT
      LAYER met2 ;
        RECT 457.330 0.000 457.610 4.000 ;
    END
  END la_oenb[18]
  PIN la_oenb[19]
    DIRECTION INPUT ;
    USE SIGNAL ;
    PORT
      LAYER met2 ;
        RECT 251.250 0.000 251.530 4.000 ;
    END
  END la_oenb[19]
  PIN la_oenb[1]
    DIRECTION INPUT ;
    USE SIGNAL ;
    PORT
      LAYER met2 ;
        RECT 334.970 896.000 335.250 900.000 ;
    END
  END la_oenb[1]
  PIN la_oenb[20]
    DIRECTION INPUT ;
    USE SIGNAL ;
    PORT
      LAYER met3 ;
        RECT 896.000 421.640 900.000 422.240 ;
    END
  END la_oenb[20]
  PIN la_oenb[21]
    DIRECTION INPUT ;
    USE SIGNAL ;
    PORT
      LAYER met3 ;
        RECT 896.000 54.440 900.000 55.040 ;
    END
  END la_oenb[21]
  PIN la_oenb[22]
    DIRECTION INPUT ;
    USE SIGNAL ;
    PORT
      LAYER met3 ;
        RECT 896.000 170.040 900.000 170.640 ;
    END
  END la_oenb[22]
  PIN la_oenb[23]
    DIRECTION INPUT ;
    USE SIGNAL ;
    PORT
      LAYER met3 ;
        RECT 0.000 241.440 4.000 242.040 ;
    END
  END la_oenb[23]
  PIN la_oenb[24]
    DIRECTION INPUT ;
    USE SIGNAL ;
    PORT
      LAYER met3 ;
        RECT 896.000 3.440 900.000 4.040 ;
    END
  END la_oenb[24]
  PIN la_oenb[25]
    DIRECTION INPUT ;
    USE SIGNAL ;
    PORT
      LAYER met3 ;
        RECT 896.000 329.840 900.000 330.440 ;
    END
  END la_oenb[25]
  PIN la_oenb[26]
    DIRECTION INPUT ;
    USE SIGNAL ;
    PORT
      LAYER met3 ;
        RECT 896.000 860.240 900.000 860.840 ;
    END
  END la_oenb[26]
  PIN la_oenb[27]
    DIRECTION INPUT ;
    USE SIGNAL ;
    PORT
      LAYER met2 ;
        RECT 54.830 0.000 55.110 4.000 ;
    END
  END la_oenb[27]
  PIN la_oenb[28]
    DIRECTION INPUT ;
    USE SIGNAL ;
    PORT
      LAYER met2 ;
        RECT 386.490 0.000 386.770 4.000 ;
    END
  END la_oenb[28]
  PIN la_oenb[29]
    DIRECTION INPUT ;
    USE SIGNAL ;
    PORT
      LAYER met2 ;
        RECT 454.110 896.000 454.390 900.000 ;
    END
  END la_oenb[29]
  PIN la_oenb[2]
    DIRECTION INPUT ;
    USE SIGNAL ;
    PORT
      LAYER met2 ;
        RECT 850.170 0.000 850.450 4.000 ;
    END
  END la_oenb[2]
  PIN la_oenb[30]
    DIRECTION INPUT ;
    USE SIGNAL ;
    PORT
      LAYER met2 ;
        RECT 45.170 0.000 45.450 4.000 ;
    END
  END la_oenb[30]
  PIN la_oenb[31]
    DIRECTION INPUT ;
    USE SIGNAL ;
    PORT
      LAYER met2 ;
        RECT 212.610 0.000 212.890 4.000 ;
    END
  END la_oenb[31]
  PIN la_oenb[32]
    DIRECTION INPUT ;
    USE SIGNAL ;
    PORT
      LAYER met2 ;
        RECT 843.730 0.000 844.010 4.000 ;
    END
  END la_oenb[32]
  PIN la_oenb[33]
    DIRECTION INPUT ;
    USE SIGNAL ;
    PORT
      LAYER met3 ;
        RECT 0.000 690.240 4.000 690.840 ;
    END
  END la_oenb[33]
  PIN la_oenb[34]
    DIRECTION INPUT ;
    USE SIGNAL ;
    PORT
      LAYER met3 ;
        RECT 896.000 146.240 900.000 146.840 ;
    END
  END la_oenb[34]
  PIN la_oenb[35]
    DIRECTION INPUT ;
    USE SIGNAL ;
    PORT
      LAYER met3 ;
        RECT 0.000 829.640 4.000 830.240 ;
    END
  END la_oenb[35]
  PIN la_oenb[36]
    DIRECTION INPUT ;
    USE SIGNAL ;
    PORT
      LAYER met3 ;
        RECT 0.000 248.240 4.000 248.840 ;
    END
  END la_oenb[36]
  PIN la_oenb[37]
    DIRECTION INPUT ;
    USE SIGNAL ;
    PORT
      LAYER met3 ;
        RECT 0.000 523.640 4.000 524.240 ;
    END
  END la_oenb[37]
  PIN la_oenb[38]
    DIRECTION INPUT ;
    USE SIGNAL ;
    PORT
      LAYER met2 ;
        RECT 605.450 896.000 605.730 900.000 ;
    END
  END la_oenb[38]
  PIN la_oenb[39]
    DIRECTION INPUT ;
    USE SIGNAL ;
    PORT
      LAYER met2 ;
        RECT 154.650 896.000 154.930 900.000 ;
    END
  END la_oenb[39]
  PIN la_oenb[3]
    DIRECTION INPUT ;
    USE SIGNAL ;
    PORT
      LAYER met3 ;
        RECT 896.000 255.040 900.000 255.640 ;
    END
  END la_oenb[3]
  PIN la_oenb[40]
    DIRECTION INPUT ;
    USE SIGNAL ;
    PORT
      LAYER met3 ;
        RECT 0.000 57.840 4.000 58.440 ;
    END
  END la_oenb[40]
  PIN la_oenb[41]
    DIRECTION INPUT ;
    USE SIGNAL ;
    PORT
      LAYER met3 ;
        RECT 0.000 115.640 4.000 116.240 ;
    END
  END la_oenb[41]
  PIN la_oenb[42]
    DIRECTION INPUT ;
    USE SIGNAL ;
    PORT
      LAYER met3 ;
        RECT 0.000 680.040 4.000 680.640 ;
    END
  END la_oenb[42]
  PIN la_oenb[43]
    DIRECTION INPUT ;
    USE SIGNAL ;
    PORT
      LAYER met2 ;
        RECT 392.930 896.000 393.210 900.000 ;
    END
  END la_oenb[43]
  PIN la_oenb[44]
    DIRECTION INPUT ;
    USE SIGNAL ;
    PORT
      LAYER met2 ;
        RECT 634.430 896.000 634.710 900.000 ;
    END
  END la_oenb[44]
  PIN la_oenb[45]
    DIRECTION INPUT ;
    USE SIGNAL ;
    PORT
      LAYER met2 ;
        RECT 241.590 0.000 241.870 4.000 ;
    END
  END la_oenb[45]
  PIN la_oenb[46]
    DIRECTION INPUT ;
    USE SIGNAL ;
    PORT
      LAYER met2 ;
        RECT 795.430 0.000 795.710 4.000 ;
    END
  END la_oenb[46]
  PIN la_oenb[47]
    DIRECTION INPUT ;
    USE SIGNAL ;
    PORT
      LAYER met2 ;
        RECT 438.010 896.000 438.290 900.000 ;
    END
  END la_oenb[47]
  PIN la_oenb[48]
    DIRECTION INPUT ;
    USE SIGNAL ;
    PORT
      LAYER met3 ;
        RECT 896.000 295.840 900.000 296.440 ;
    END
  END la_oenb[48]
  PIN la_oenb[49]
    DIRECTION INPUT ;
    USE SIGNAL ;
    PORT
      LAYER met2 ;
        RECT 779.330 896.000 779.610 900.000 ;
    END
  END la_oenb[49]
  PIN la_oenb[4]
    DIRECTION INPUT ;
    USE SIGNAL ;
    PORT
      LAYER met2 ;
        RECT 582.910 0.000 583.190 4.000 ;
    END
  END la_oenb[4]
  PIN la_oenb[50]
    DIRECTION INPUT ;
    USE SIGNAL ;
    PORT
      LAYER met3 ;
        RECT 0.000 530.440 4.000 531.040 ;
    END
  END la_oenb[50]
  PIN la_oenb[51]
    DIRECTION INPUT ;
    USE SIGNAL ;
    PORT
      LAYER met3 ;
        RECT 896.000 377.440 900.000 378.040 ;
    END
  END la_oenb[51]
  PIN la_oenb[52]
    DIRECTION INPUT ;
    USE SIGNAL ;
    PORT
      LAYER met3 ;
        RECT 896.000 703.840 900.000 704.440 ;
    END
  END la_oenb[52]
  PIN la_oenb[53]
    DIRECTION INPUT ;
    USE SIGNAL ;
    PORT
      LAYER met3 ;
        RECT 0.000 207.440 4.000 208.040 ;
    END
  END la_oenb[53]
  PIN la_oenb[54]
    DIRECTION INPUT ;
    USE SIGNAL ;
    PORT
      LAYER met2 ;
        RECT 161.090 896.000 161.370 900.000 ;
    END
  END la_oenb[54]
  PIN la_oenb[55]
    DIRECTION INPUT ;
    USE SIGNAL ;
    PORT
      LAYER met3 ;
        RECT 896.000 578.040 900.000 578.640 ;
    END
  END la_oenb[55]
  PIN la_oenb[56]
    DIRECTION INPUT ;
    USE SIGNAL ;
    PORT
      LAYER met3 ;
        RECT 0.000 897.640 4.000 898.240 ;
    END
  END la_oenb[56]
  PIN la_oenb[57]
    DIRECTION INPUT ;
    USE SIGNAL ;
    PORT
      LAYER met2 ;
        RECT 383.270 896.000 383.550 900.000 ;
    END
  END la_oenb[57]
  PIN la_oenb[58]
    DIRECTION INPUT ;
    USE SIGNAL ;
    PORT
      LAYER met3 ;
        RECT 0.000 489.640 4.000 490.240 ;
    END
  END la_oenb[58]
  PIN la_oenb[59]
    DIRECTION INPUT ;
    USE SIGNAL ;
    PORT
      LAYER met2 ;
        RECT 202.950 0.000 203.230 4.000 ;
    END
  END la_oenb[59]
  PIN la_oenb[5]
    DIRECTION INPUT ;
    USE SIGNAL ;
    PORT
      LAYER met2 ;
        RECT 202.950 896.000 203.230 900.000 ;
    END
  END la_oenb[5]
  PIN la_oenb[60]
    DIRECTION INPUT ;
    USE SIGNAL ;
    PORT
      LAYER met2 ;
        RECT 99.910 896.000 100.190 900.000 ;
    END
  END la_oenb[60]
  PIN la_oenb[61]
    DIRECTION INPUT ;
    USE SIGNAL ;
    PORT
      LAYER met2 ;
        RECT 360.730 896.000 361.010 900.000 ;
    END
  END la_oenb[61]
  PIN la_oenb[62]
    DIRECTION INPUT ;
    USE SIGNAL ;
    PORT
      LAYER met2 ;
        RECT 753.570 896.000 753.850 900.000 ;
    END
  END la_oenb[62]
  PIN la_oenb[63]
    DIRECTION INPUT ;
    USE SIGNAL ;
    PORT
      LAYER met2 ;
        RECT 721.370 896.000 721.650 900.000 ;
    END
  END la_oenb[63]
  PIN la_oenb[64]
    DIRECTION INPUT ;
    USE SIGNAL ;
    PORT
      LAYER met3 ;
        RECT 0.000 380.840 4.000 381.440 ;
    END
  END la_oenb[64]
  PIN la_oenb[65]
    DIRECTION INPUT ;
    USE SIGNAL ;
    PORT
      LAYER met2 ;
        RECT 257.690 0.000 257.970 4.000 ;
    END
  END la_oenb[65]
  PIN la_oenb[66]
    DIRECTION INPUT ;
    USE SIGNAL ;
    PORT
      LAYER met2 ;
        RECT 138.550 896.000 138.830 900.000 ;
    END
  END la_oenb[66]
  PIN la_oenb[67]
    DIRECTION INPUT ;
    USE SIGNAL ;
    PORT
      LAYER met2 ;
        RECT 811.530 0.000 811.810 4.000 ;
    END
  END la_oenb[67]
  PIN la_oenb[68]
    DIRECTION INPUT ;
    USE SIGNAL ;
    PORT
      LAYER met2 ;
        RECT 541.050 896.000 541.330 900.000 ;
    END
  END la_oenb[68]
  PIN la_oenb[69]
    DIRECTION INPUT ;
    USE SIGNAL ;
    PORT
      LAYER met2 ;
        RECT 164.310 0.000 164.590 4.000 ;
    END
  END la_oenb[69]
  PIN la_oenb[6]
    DIRECTION INPUT ;
    USE SIGNAL ;
    PORT
      LAYER met3 ;
        RECT 0.000 306.040 4.000 306.640 ;
    END
  END la_oenb[6]
  PIN la_oenb[70]
    DIRECTION INPUT ;
    USE SIGNAL ;
    PORT
      LAYER met2 ;
        RECT 879.150 896.000 879.430 900.000 ;
    END
  END la_oenb[70]
  PIN la_oenb[71]
    DIRECTION INPUT ;
    USE SIGNAL ;
    PORT
      LAYER met2 ;
        RECT 824.410 896.000 824.690 900.000 ;
    END
  END la_oenb[71]
  PIN la_oenb[72]
    DIRECTION INPUT ;
    USE SIGNAL ;
    PORT
      LAYER met3 ;
        RECT 0.000 190.440 4.000 191.040 ;
    END
  END la_oenb[72]
  PIN la_oenb[73]
    DIRECTION INPUT ;
    USE SIGNAL ;
    PORT
      LAYER met3 ;
        RECT 896.000 795.640 900.000 796.240 ;
    END
  END la_oenb[73]
  PIN la_oenb[74]
    DIRECTION INPUT ;
    USE SIGNAL ;
    PORT
      LAYER met3 ;
        RECT 896.000 785.440 900.000 786.040 ;
    END
  END la_oenb[74]
  PIN la_oenb[75]
    DIRECTION INPUT ;
    USE SIGNAL ;
    PORT
      LAYER met2 ;
        RECT 463.770 0.000 464.050 4.000 ;
    END
  END la_oenb[75]
  PIN la_oenb[76]
    DIRECTION INPUT ;
    USE SIGNAL ;
    PORT
      LAYER met3 ;
        RECT 0.000 431.840 4.000 432.440 ;
    END
  END la_oenb[76]
  PIN la_oenb[77]
    DIRECTION INPUT ;
    USE SIGNAL ;
    PORT
      LAYER met2 ;
        RECT 235.150 896.000 235.430 900.000 ;
    END
  END la_oenb[77]
  PIN la_oenb[78]
    DIRECTION INPUT ;
    USE SIGNAL ;
    PORT
      LAYER met2 ;
        RECT 6.530 0.000 6.810 4.000 ;
    END
  END la_oenb[78]
  PIN la_oenb[79]
    DIRECTION INPUT ;
    USE SIGNAL ;
    PORT
      LAYER met3 ;
        RECT 0.000 649.440 4.000 650.040 ;
    END
  END la_oenb[79]
  PIN la_oenb[7]
    DIRECTION INPUT ;
    USE SIGNAL ;
    PORT
      LAYER met2 ;
        RECT 470.210 0.000 470.490 4.000 ;
    END
  END la_oenb[7]
  PIN la_oenb[80]
    DIRECTION INPUT ;
    USE SIGNAL ;
    PORT
      LAYER met3 ;
        RECT 896.000 44.240 900.000 44.840 ;
    END
  END la_oenb[80]
  PIN la_oenb[81]
    DIRECTION INPUT ;
    USE SIGNAL ;
    PORT
      LAYER met3 ;
        RECT 0.000 754.840 4.000 755.440 ;
    END
  END la_oenb[81]
  PIN la_oenb[82]
    DIRECTION INPUT ;
    USE SIGNAL ;
    PORT
      LAYER met3 ;
        RECT 896.000 119.040 900.000 119.640 ;
    END
  END la_oenb[82]
  PIN la_oenb[83]
    DIRECTION INPUT ;
    USE SIGNAL ;
    PORT
      LAYER met3 ;
        RECT 0.000 156.440 4.000 157.040 ;
    END
  END la_oenb[83]
  PIN la_oenb[84]
    DIRECTION INPUT ;
    USE SIGNAL ;
    PORT
      LAYER met2 ;
        RECT 29.070 0.000 29.350 4.000 ;
    END
  END la_oenb[84]
  PIN la_oenb[85]
    DIRECTION INPUT ;
    USE SIGNAL ;
    PORT
      LAYER met3 ;
        RECT 0.000 180.240 4.000 180.840 ;
    END
  END la_oenb[85]
  PIN la_oenb[86]
    DIRECTION INPUT ;
    USE SIGNAL ;
    PORT
      LAYER met2 ;
        RECT 399.370 0.000 399.650 4.000 ;
    END
  END la_oenb[86]
  PIN la_oenb[87]
    DIRECTION INPUT ;
    USE SIGNAL ;
    PORT
      LAYER met2 ;
        RECT 692.390 896.000 692.670 900.000 ;
    END
  END la_oenb[87]
  PIN la_oenb[88]
    DIRECTION INPUT ;
    USE SIGNAL ;
    PORT
      LAYER met3 ;
        RECT 0.000 564.440 4.000 565.040 ;
    END
  END la_oenb[88]
  PIN la_oenb[89]
    DIRECTION INPUT ;
    USE SIGNAL ;
    PORT
      LAYER met3 ;
        RECT 0.000 574.640 4.000 575.240 ;
    END
  END la_oenb[89]
  PIN la_oenb[8]
    DIRECTION INPUT ;
    USE SIGNAL ;
    PORT
      LAYER met2 ;
        RECT 676.290 0.000 676.570 4.000 ;
    END
  END la_oenb[8]
  PIN la_oenb[90]
    DIRECTION INPUT ;
    USE SIGNAL ;
    PORT
      LAYER met3 ;
        RECT 896.000 462.440 900.000 463.040 ;
    END
  END la_oenb[90]
  PIN la_oenb[91]
    DIRECTION INPUT ;
    USE SIGNAL ;
    PORT
      LAYER met3 ;
        RECT 896.000 635.840 900.000 636.440 ;
    END
  END la_oenb[91]
  PIN la_oenb[92]
    DIRECTION INPUT ;
    USE SIGNAL ;
    PORT
      LAYER met2 ;
        RECT 702.050 0.000 702.330 4.000 ;
    END
  END la_oenb[92]
  PIN la_oenb[93]
    DIRECTION INPUT ;
    USE SIGNAL ;
    PORT
      LAYER met2 ;
        RECT 241.590 896.000 241.870 900.000 ;
    END
  END la_oenb[93]
  PIN la_oenb[94]
    DIRECTION INPUT ;
    USE SIGNAL ;
    PORT
      LAYER met3 ;
        RECT 0.000 605.240 4.000 605.840 ;
    END
  END la_oenb[94]
  PIN la_oenb[95]
    DIRECTION INPUT ;
    USE SIGNAL ;
    PORT
      LAYER met3 ;
        RECT 896.000 605.240 900.000 605.840 ;
    END
  END la_oenb[95]
  PIN la_oenb[96]
    DIRECTION INPUT ;
    USE SIGNAL ;
    PORT
      LAYER met2 ;
        RECT 557.150 896.000 557.430 900.000 ;
    END
  END la_oenb[96]
  PIN la_oenb[97]
    DIRECTION INPUT ;
    USE SIGNAL ;
    PORT
      LAYER met3 ;
        RECT 896.000 486.240 900.000 486.840 ;
    END
  END la_oenb[97]
  PIN la_oenb[98]
    DIRECTION INPUT ;
    USE SIGNAL ;
    PORT
      LAYER met2 ;
        RECT 685.950 0.000 686.230 4.000 ;
    END
  END la_oenb[98]
  PIN la_oenb[99]
    DIRECTION INPUT ;
    USE SIGNAL ;
    PORT
      LAYER met2 ;
        RECT 747.130 896.000 747.410 900.000 ;
    END
  END la_oenb[99]
  PIN la_oenb[9]
    DIRECTION INPUT ;
    USE SIGNAL ;
    PORT
      LAYER met3 ;
        RECT 896.000 95.240 900.000 95.840 ;
    END
  END la_oenb[9]
  PIN pwm_fall_out
    DIRECTION OUTPUT TRISTATE ;
    USE SIGNAL ;
    ANTENNADIFFAREA 0.795200 ;
    PORT
      LAYER met2 ;
        RECT 486.310 896.000 486.590 900.000 ;
    END
  END pwm_fall_out
  PIN pwm_rise_out
    DIRECTION OUTPUT TRISTATE ;
    USE SIGNAL ;
    ANTENNADIFFAREA 0.445500 ;
    PORT
      LAYER met2 ;
        RECT 834.070 0.000 834.350 4.000 ;
    END
  END pwm_rise_out
  PIN user_clock2
    DIRECTION INPUT ;
    USE SIGNAL ;
    PORT
      LAYER met2 ;
        RECT 170.750 896.000 171.030 900.000 ;
    END
  END user_clock2
  PIN user_irq[0]
    DIRECTION OUTPUT TRISTATE ;
    USE SIGNAL ;
    ANTENNADIFFAREA 0.445500 ;
    PORT
      LAYER met2 ;
        RECT 109.570 0.000 109.850 4.000 ;
    END
  END user_irq[0]
  PIN user_irq[1]
    DIRECTION OUTPUT TRISTATE ;
    USE SIGNAL ;
    ANTENNADIFFAREA 0.445500 ;
    PORT
      LAYER met3 ;
        RECT 896.000 469.240 900.000 469.840 ;
    END
  END user_irq[1]
  PIN user_irq[2]
    DIRECTION OUTPUT TRISTATE ;
    USE SIGNAL ;
    ANTENNADIFFAREA 0.445500 ;
    PORT
      LAYER met3 ;
        RECT 0.000 822.840 4.000 823.440 ;
    END
  END user_irq[2]
  PIN vccd1
    DIRECTION INOUT ;
    USE POWER ;
    PORT
      LAYER met3 ;
        RECT 896.000 618.840 900.000 619.440 ;
    END
    PORT
      LAYER met4 ;
        RECT 21.040 10.640 22.640 886.960 ;
    END
    PORT
      LAYER met4 ;
        RECT 174.640 10.640 176.240 886.960 ;
    END
    PORT
      LAYER met4 ;
        RECT 328.240 10.640 329.840 886.960 ;
    END
    PORT
      LAYER met4 ;
        RECT 481.840 10.640 483.440 886.960 ;
    END
    PORT
      LAYER met4 ;
        RECT 635.440 10.640 637.040 886.960 ;
    END
    PORT
      LAYER met4 ;
        RECT 789.040 10.640 790.640 886.960 ;
    END
  END vccd1
  PIN vccd2
    DIRECTION INOUT ;
    USE SIGNAL ;
    PORT
      LAYER met2 ;
        RECT 228.710 0.000 228.990 4.000 ;
    END
  END vccd2
  PIN vdda1
    DIRECTION INOUT ;
    USE SIGNAL ;
    PORT
      LAYER met2 ;
        RECT 856.610 0.000 856.890 4.000 ;
    END
  END vdda1
  PIN vdda2
    DIRECTION INOUT ;
    USE SIGNAL ;
    PORT
      LAYER met2 ;
        RECT 225.490 896.000 225.770 900.000 ;
    END
  END vdda2
  PIN vssa1
    DIRECTION INOUT ;
    USE SIGNAL ;
    PORT
      LAYER met2 ;
        RECT 731.030 896.000 731.310 900.000 ;
    END
  END vssa1
  PIN vssa2
    DIRECTION INOUT ;
    USE SIGNAL ;
    PORT
      LAYER met3 ;
        RECT 0.000 455.640 4.000 456.240 ;
    END
  END vssa2
  PIN vssd1
    DIRECTION INOUT ;
    USE GROUND ;
    PORT
      LAYER met2 ;
        RECT 186.850 896.000 187.130 900.000 ;
    END
    PORT
      LAYER met4 ;
        RECT 97.840 10.640 99.440 886.960 ;
    END
    PORT
      LAYER met4 ;
        RECT 251.440 10.640 253.040 886.960 ;
    END
    PORT
      LAYER met4 ;
        RECT 405.040 10.640 406.640 886.960 ;
    END
    PORT
      LAYER met4 ;
        RECT 558.640 10.640 560.240 886.960 ;
    END
    PORT
      LAYER met4 ;
        RECT 712.240 10.640 713.840 886.960 ;
    END
    PORT
      LAYER met4 ;
        RECT 865.840 10.640 867.440 886.960 ;
    END
  END vssd1
  PIN vssd2
    DIRECTION INOUT ;
    USE SIGNAL ;
    PORT
      LAYER met3 ;
        RECT 0.000 588.240 4.000 588.840 ;
    END
  END vssd2
  PIN wb_clk_i
    DIRECTION INPUT ;
    USE SIGNAL ;
    ANTENNAGATEAREA 0.213000 ;
    PORT
      LAYER met3 ;
        RECT 896.000 163.240 900.000 163.840 ;
    END
  END wb_clk_i
  PIN wb_rst_i
    DIRECTION INPUT ;
    USE SIGNAL ;
    PORT
      LAYER met2 ;
        RECT 132.110 896.000 132.390 900.000 ;
    END
  END wb_rst_i
  PIN wbs_ack_o
    DIRECTION OUTPUT TRISTATE ;
    USE SIGNAL ;
    ANTENNADIFFAREA 0.445500 ;
    PORT
      LAYER met3 ;
        RECT 896.000 319.640 900.000 320.240 ;
    END
  END wbs_ack_o
  PIN wbs_adr_i[0]
    DIRECTION INPUT ;
    USE SIGNAL ;
    ANTENNAGATEAREA 0.247500 ;
    PORT
      LAYER met2 ;
        RECT 563.590 896.000 563.870 900.000 ;
    END
  END wbs_adr_i[0]
  PIN wbs_adr_i[10]
    DIRECTION INPUT ;
    USE SIGNAL ;
    ANTENNAGATEAREA 0.247500 ;
    PORT
      LAYER met2 ;
        RECT 376.830 896.000 377.110 900.000 ;
    END
  END wbs_adr_i[10]
  PIN wbs_adr_i[11]
    DIRECTION INPUT ;
    USE SIGNAL ;
    ANTENNAGATEAREA 0.742500 ;
    PORT
      LAYER met2 ;
        RECT 19.410 896.000 19.690 900.000 ;
    END
  END wbs_adr_i[11]
  PIN wbs_adr_i[12]
    DIRECTION INPUT ;
    USE SIGNAL ;
    ANTENNAGATEAREA 0.495000 ;
    PORT
      LAYER met2 ;
        RECT 77.370 0.000 77.650 4.000 ;
    END
  END wbs_adr_i[12]
  PIN wbs_adr_i[13]
    DIRECTION INPUT ;
    USE SIGNAL ;
    ANTENNAGATEAREA 0.247500 ;
    PORT
      LAYER met3 ;
        RECT 0.000 748.040 4.000 748.640 ;
    END
  END wbs_adr_i[13]
  PIN wbs_adr_i[14]
    DIRECTION INPUT ;
    USE SIGNAL ;
    ANTENNAGATEAREA 0.213000 ;
    PORT
      LAYER met3 ;
        RECT 896.000 686.840 900.000 687.440 ;
    END
  END wbs_adr_i[14]
  PIN wbs_adr_i[15]
    DIRECTION INPUT ;
    USE SIGNAL ;
    ANTENNAGATEAREA 0.159000 ;
    PORT
      LAYER met3 ;
        RECT 896.000 629.040 900.000 629.640 ;
    END
  END wbs_adr_i[15]
  PIN wbs_adr_i[16]
    DIRECTION INPUT ;
    USE SIGNAL ;
    ANTENNAGATEAREA 0.159000 ;
    PORT
      LAYER met2 ;
        RECT 566.810 0.000 567.090 4.000 ;
    END
  END wbs_adr_i[16]
  PIN wbs_adr_i[17]
    DIRECTION INPUT ;
    USE SIGNAL ;
    ANTENNAGATEAREA 0.247500 ;
    PORT
      LAYER met3 ;
        RECT 896.000 561.040 900.000 561.640 ;
    END
  END wbs_adr_i[17]
  PIN wbs_adr_i[18]
    DIRECTION INPUT ;
    USE SIGNAL ;
    ANTENNAGATEAREA 0.247500 ;
    PORT
      LAYER met3 ;
        RECT 0.000 448.840 4.000 449.440 ;
    END
  END wbs_adr_i[18]
  PIN wbs_adr_i[19]
    DIRECTION INPUT ;
    USE SIGNAL ;
    ANTENNAGATEAREA 0.247500 ;
    PORT
      LAYER met2 ;
        RECT 866.270 0.000 866.550 4.000 ;
    END
  END wbs_adr_i[19]
  PIN wbs_adr_i[1]
    DIRECTION INPUT ;
    USE SIGNAL ;
    ANTENNAGATEAREA 0.247500 ;
    PORT
      LAYER met2 ;
        RECT 547.490 896.000 547.770 900.000 ;
    END
  END wbs_adr_i[1]
  PIN wbs_adr_i[20]
    DIRECTION INPUT ;
    USE SIGNAL ;
    ANTENNAGATEAREA 0.426000 ;
    PORT
      LAYER met2 ;
        RECT 801.870 896.000 802.150 900.000 ;
    END
  END wbs_adr_i[20]
  PIN wbs_adr_i[21]
    DIRECTION INPUT ;
    USE SIGNAL ;
    ANTENNAGATEAREA 0.159000 ;
    PORT
      LAYER met2 ;
        RECT 502.410 0.000 502.690 4.000 ;
    END
  END wbs_adr_i[21]
  PIN wbs_adr_i[22]
    DIRECTION INPUT ;
    USE SIGNAL ;
    ANTENNAGATEAREA 0.247500 ;
    PORT
      LAYER met3 ;
        RECT 0.000 397.840 4.000 398.440 ;
    END
  END wbs_adr_i[22]
  PIN wbs_adr_i[23]
    DIRECTION INPUT ;
    USE SIGNAL ;
    ANTENNAGATEAREA 0.213000 ;
    PORT
      LAYER met3 ;
        RECT 896.000 204.040 900.000 204.640 ;
    END
  END wbs_adr_i[23]
  PIN wbs_adr_i[24]
    DIRECTION INPUT ;
    USE SIGNAL ;
    ANTENNAGATEAREA 0.426000 ;
    PORT
      LAYER met2 ;
        RECT 83.810 896.000 84.090 900.000 ;
    END
  END wbs_adr_i[24]
  PIN wbs_adr_i[25]
    DIRECTION INPUT ;
    USE SIGNAL ;
    ANTENNAGATEAREA 0.213000 ;
    PORT
      LAYER met2 ;
        RECT 486.310 0.000 486.590 4.000 ;
    END
  END wbs_adr_i[25]
  PIN wbs_adr_i[26]
    DIRECTION INPUT ;
    USE SIGNAL ;
    ANTENNAGATEAREA 0.213000 ;
    PORT
      LAYER met2 ;
        RECT 93.470 0.000 93.750 4.000 ;
    END
  END wbs_adr_i[26]
  PIN wbs_adr_i[27]
    DIRECTION INPUT ;
    USE SIGNAL ;
    ANTENNAGATEAREA 0.247500 ;
    PORT
      LAYER met2 ;
        RECT 280.230 896.000 280.510 900.000 ;
    END
  END wbs_adr_i[27]
  PIN wbs_adr_i[28]
    DIRECTION INPUT ;
    USE SIGNAL ;
    ANTENNAGATEAREA 0.213000 ;
    PORT
      LAYER met3 ;
        RECT 896.000 537.240 900.000 537.840 ;
    END
  END wbs_adr_i[28]
  PIN wbs_adr_i[29]
    DIRECTION INPUT ;
    USE SIGNAL ;
    ANTENNAGATEAREA 0.213000 ;
    PORT
      LAYER met3 ;
        RECT 896.000 894.240 900.000 894.840 ;
    END
  END wbs_adr_i[29]
  PIN wbs_adr_i[2]
    DIRECTION INPUT ;
    USE SIGNAL ;
    ANTENNAGATEAREA 0.213000 ;
    PORT
      LAYER met2 ;
        RECT 344.630 0.000 344.910 4.000 ;
    END
  END wbs_adr_i[2]
  PIN wbs_adr_i[30]
    DIRECTION INPUT ;
    USE SIGNAL ;
    ANTENNAGATEAREA 0.159000 ;
    PORT
      LAYER met2 ;
        RECT 682.730 896.000 683.010 900.000 ;
    END
  END wbs_adr_i[30]
  PIN wbs_adr_i[31]
    DIRECTION INPUT ;
    USE SIGNAL ;
    ANTENNAGATEAREA 0.426000 ;
    PORT
      LAYER met3 ;
        RECT 0.000 346.840 4.000 347.440 ;
    END
  END wbs_adr_i[31]
  PIN wbs_adr_i[3]
    DIRECTION INPUT ;
    USE SIGNAL ;
    ANTENNAGATEAREA 0.247500 ;
    PORT
      LAYER met3 ;
        RECT 0.000 224.440 4.000 225.040 ;
    END
  END wbs_adr_i[3]
  PIN wbs_adr_i[4]
    DIRECTION INPUT ;
    USE SIGNAL ;
    ANTENNAGATEAREA 0.213000 ;
    PORT
      LAYER met3 ;
        RECT 0.000 282.240 4.000 282.840 ;
    END
  END wbs_adr_i[4]
  PIN wbs_adr_i[5]
    DIRECTION INPUT ;
    USE SIGNAL ;
    ANTENNAGATEAREA 0.247500 ;
    PORT
      LAYER met2 ;
        RECT 669.850 0.000 670.130 4.000 ;
    END
  END wbs_adr_i[5]
  PIN wbs_adr_i[6]
    DIRECTION INPUT ;
    USE SIGNAL ;
    ANTENNAGATEAREA 0.213000 ;
    PORT
      LAYER met2 ;
        RECT 283.450 0.000 283.730 4.000 ;
    END
  END wbs_adr_i[6]
  PIN wbs_adr_i[7]
    DIRECTION INPUT ;
    USE SIGNAL ;
    ANTENNAGATEAREA 0.213000 ;
    PORT
      LAYER met3 ;
        RECT 0.000 547.440 4.000 548.040 ;
    END
  END wbs_adr_i[7]
  PIN wbs_adr_i[8]
    DIRECTION INPUT ;
    USE SIGNAL ;
    ANTENNAGATEAREA 0.247500 ;
    PORT
      LAYER met2 ;
        RECT 888.810 0.000 889.090 4.000 ;
    END
  END wbs_adr_i[8]
  PIN wbs_adr_i[9]
    DIRECTION INPUT ;
    USE SIGNAL ;
    ANTENNAGATEAREA 0.159000 ;
    PORT
      LAYER met3 ;
        RECT 896.000 244.840 900.000 245.440 ;
    END
  END wbs_adr_i[9]
  PIN wbs_cyc_i
    DIRECTION INPUT ;
    USE SIGNAL ;
    ANTENNAGATEAREA 0.247500 ;
    PORT
      LAYER met2 ;
        RECT 264.130 896.000 264.410 900.000 ;
    END
  END wbs_cyc_i
  PIN wbs_dat_i[0]
    DIRECTION INPUT ;
    USE SIGNAL ;
    ANTENNAGATEAREA 0.426000 ;
    PORT
      LAYER met3 ;
        RECT 896.000 802.440 900.000 803.040 ;
    END
  END wbs_dat_i[0]
  PIN wbs_dat_i[10]
    DIRECTION INPUT ;
    USE SIGNAL ;
    PORT
      LAYER met3 ;
        RECT 0.000 673.240 4.000 673.840 ;
    END
  END wbs_dat_i[10]
  PIN wbs_dat_i[11]
    DIRECTION INPUT ;
    USE SIGNAL ;
    PORT
      LAYER met3 ;
        RECT 0.000 737.840 4.000 738.440 ;
    END
  END wbs_dat_i[11]
  PIN wbs_dat_i[12]
    DIRECTION INPUT ;
    USE SIGNAL ;
    PORT
      LAYER met3 ;
        RECT 0.000 714.040 4.000 714.640 ;
    END
  END wbs_dat_i[12]
  PIN wbs_dat_i[13]
    DIRECTION INPUT ;
    USE SIGNAL ;
    PORT
      LAYER met2 ;
        RECT 38.730 0.000 39.010 4.000 ;
    END
  END wbs_dat_i[13]
  PIN wbs_dat_i[14]
    DIRECTION INPUT ;
    USE SIGNAL ;
    PORT
      LAYER met2 ;
        RECT 186.850 0.000 187.130 4.000 ;
    END
  END wbs_dat_i[14]
  PIN wbs_dat_i[15]
    DIRECTION INPUT ;
    USE SIGNAL ;
    PORT
      LAYER met3 ;
        RECT 896.000 479.440 900.000 480.040 ;
    END
  END wbs_dat_i[15]
  PIN wbs_dat_i[16]
    DIRECTION INPUT ;
    USE SIGNAL ;
    PORT
      LAYER met2 ;
        RECT 512.070 0.000 512.350 4.000 ;
    END
  END wbs_dat_i[16]
  PIN wbs_dat_i[17]
    DIRECTION INPUT ;
    USE SIGNAL ;
    PORT
      LAYER met3 ;
        RECT 0.000 64.640 4.000 65.240 ;
    END
  END wbs_dat_i[17]
  PIN wbs_dat_i[18]
    DIRECTION INPUT ;
    USE SIGNAL ;
    PORT
      LAYER met2 ;
        RECT 817.970 896.000 818.250 900.000 ;
    END
  END wbs_dat_i[18]
  PIN wbs_dat_i[19]
    DIRECTION INPUT ;
    USE SIGNAL ;
    PORT
      LAYER met2 ;
        RECT 45.170 896.000 45.450 900.000 ;
    END
  END wbs_dat_i[19]
  PIN wbs_dat_i[1]
    DIRECTION INPUT ;
    USE SIGNAL ;
    ANTENNAGATEAREA 0.247500 ;
    PORT
      LAYER met2 ;
        RECT 132.110 0.000 132.390 4.000 ;
    END
  END wbs_dat_i[1]
  PIN wbs_dat_i[20]
    DIRECTION INPUT ;
    USE SIGNAL ;
    PORT
      LAYER met3 ;
        RECT 0.000 408.040 4.000 408.640 ;
    END
  END wbs_dat_i[20]
  PIN wbs_dat_i[21]
    DIRECTION INPUT ;
    USE SIGNAL ;
    PORT
      LAYER met2 ;
        RECT 840.510 896.000 840.790 900.000 ;
    END
  END wbs_dat_i[21]
  PIN wbs_dat_i[22]
    DIRECTION INPUT ;
    USE SIGNAL ;
    PORT
      LAYER met3 ;
        RECT 0.000 513.440 4.000 514.040 ;
    END
  END wbs_dat_i[22]
  PIN wbs_dat_i[23]
    DIRECTION INPUT ;
    USE SIGNAL ;
    PORT
      LAYER met3 ;
        RECT 896.000 720.840 900.000 721.440 ;
    END
  END wbs_dat_i[23]
  PIN wbs_dat_i[24]
    DIRECTION INPUT ;
    USE SIGNAL ;
    PORT
      LAYER met3 ;
        RECT 896.000 285.640 900.000 286.240 ;
    END
  END wbs_dat_i[24]
  PIN wbs_dat_i[25]
    DIRECTION INPUT ;
    USE SIGNAL ;
    PORT
      LAYER met2 ;
        RECT 615.110 0.000 615.390 4.000 ;
    END
  END wbs_dat_i[25]
  PIN wbs_dat_i[26]
    DIRECTION INPUT ;
    USE SIGNAL ;
    PORT
      LAYER met2 ;
        RECT 737.470 896.000 737.750 900.000 ;
    END
  END wbs_dat_i[26]
  PIN wbs_dat_i[27]
    DIRECTION INPUT ;
    USE SIGNAL ;
    PORT
      LAYER met2 ;
        RECT 209.390 896.000 209.670 900.000 ;
    END
  END wbs_dat_i[27]
  PIN wbs_dat_i[28]
    DIRECTION INPUT ;
    USE SIGNAL ;
    PORT
      LAYER met2 ;
        RECT 273.790 0.000 274.070 4.000 ;
    END
  END wbs_dat_i[28]
  PIN wbs_dat_i[29]
    DIRECTION INPUT ;
    USE SIGNAL ;
    PORT
      LAYER met3 ;
        RECT 896.000 554.240 900.000 554.840 ;
    END
  END wbs_dat_i[29]
  PIN wbs_dat_i[2]
    DIRECTION INPUT ;
    USE SIGNAL ;
    ANTENNAGATEAREA 0.213000 ;
    PORT
      LAYER met2 ;
        RECT 724.590 0.000 724.870 4.000 ;
    END
  END wbs_dat_i[2]
  PIN wbs_dat_i[30]
    DIRECTION INPUT ;
    USE SIGNAL ;
    PORT
      LAYER met3 ;
        RECT 896.000 261.840 900.000 262.440 ;
    END
  END wbs_dat_i[30]
  PIN wbs_dat_i[31]
    DIRECTION INPUT ;
    USE SIGNAL ;
    PORT
      LAYER met3 ;
        RECT 0.000 465.840 4.000 466.440 ;
    END
  END wbs_dat_i[31]
  PIN wbs_dat_i[3]
    DIRECTION INPUT ;
    USE SIGNAL ;
    ANTENNAGATEAREA 0.247500 ;
    PORT
      LAYER met3 ;
        RECT 896.000 20.440 900.000 21.040 ;
    END
  END wbs_dat_i[3]
  PIN wbs_dat_i[4]
    DIRECTION INPUT ;
    USE SIGNAL ;
    ANTENNAGATEAREA 0.247500 ;
    PORT
      LAYER met2 ;
        RECT 141.770 0.000 142.050 4.000 ;
    END
  END wbs_dat_i[4]
  PIN wbs_dat_i[5]
    DIRECTION INPUT ;
    USE SIGNAL ;
    ANTENNAGATEAREA 0.213000 ;
    PORT
      LAYER met2 ;
        RECT 441.230 0.000 441.510 4.000 ;
    END
  END wbs_dat_i[5]
  PIN wbs_dat_i[6]
    DIRECTION INPUT ;
    USE SIGNAL ;
    ANTENNAGATEAREA 0.213000 ;
    PORT
      LAYER met3 ;
        RECT 896.000 387.640 900.000 388.240 ;
    END
  END wbs_dat_i[6]
  PIN wbs_dat_i[7]
    DIRECTION INPUT ;
    USE SIGNAL ;
    ANTENNAGATEAREA 0.247500 ;
    PORT
      LAYER met2 ;
        RECT 705.270 896.000 705.550 900.000 ;
    END
  END wbs_dat_i[7]
  PIN wbs_dat_i[8]
    DIRECTION INPUT ;
    USE SIGNAL ;
    PORT
      LAYER met3 ;
        RECT 896.000 819.440 900.000 820.040 ;
    END
  END wbs_dat_i[8]
  PIN wbs_dat_i[9]
    DIRECTION INPUT ;
    USE SIGNAL ;
    PORT
      LAYER met3 ;
        RECT 896.000 30.640 900.000 31.240 ;
    END
  END wbs_dat_i[9]
  PIN wbs_dat_o[0]
    DIRECTION OUTPUT TRISTATE ;
    USE SIGNAL ;
    ANTENNADIFFAREA 0.445500 ;
    PORT
      LAYER met2 ;
        RECT 70.930 0.000 71.210 4.000 ;
    END
  END wbs_dat_o[0]
  PIN wbs_dat_o[10]
    DIRECTION OUTPUT TRISTATE ;
    USE SIGNAL ;
    ANTENNADIFFAREA 0.445500 ;
    PORT
      LAYER met3 ;
        RECT 896.000 513.440 900.000 514.040 ;
    END
  END wbs_dat_o[10]
  PIN wbs_dat_o[11]
    DIRECTION OUTPUT TRISTATE ;
    USE SIGNAL ;
    ANTENNADIFFAREA 0.445500 ;
    PORT
      LAYER met2 ;
        RECT 12.970 0.000 13.250 4.000 ;
    END
  END wbs_dat_o[11]
  PIN wbs_dat_o[12]
    DIRECTION OUTPUT TRISTATE ;
    USE SIGNAL ;
    ANTENNADIFFAREA 0.445500 ;
    PORT
      LAYER met3 ;
        RECT 896.000 836.440 900.000 837.040 ;
    END
  END wbs_dat_o[12]
  PIN wbs_dat_o[13]
    DIRECTION OUTPUT TRISTATE ;
    USE SIGNAL ;
    ANTENNADIFFAREA 0.445500 ;
    PORT
      LAYER met2 ;
        RECT 666.630 896.000 666.910 900.000 ;
    END
  END wbs_dat_o[13]
  PIN wbs_dat_o[14]
    DIRECTION OUTPUT TRISTATE ;
    USE SIGNAL ;
    ANTENNADIFFAREA 0.445500 ;
    PORT
      LAYER met3 ;
        RECT 896.000 88.440 900.000 89.040 ;
    END
  END wbs_dat_o[14]
  PIN wbs_dat_o[15]
    DIRECTION OUTPUT TRISTATE ;
    USE SIGNAL ;
    ANTENNADIFFAREA 0.445500 ;
    PORT
      LAYER met2 ;
        RECT 644.090 896.000 644.370 900.000 ;
    END
  END wbs_dat_o[15]
  PIN wbs_dat_o[16]
    DIRECTION OUTPUT TRISTATE ;
    USE SIGNAL ;
    ANTENNADIFFAREA 0.445500 ;
    PORT
      LAYER met2 ;
        RECT 599.010 0.000 599.290 4.000 ;
    END
  END wbs_dat_o[16]
  PIN wbs_dat_o[17]
    DIRECTION OUTPUT TRISTATE ;
    USE SIGNAL ;
    ANTENNADIFFAREA 0.445500 ;
    PORT
      LAYER met3 ;
        RECT 0.000 272.040 4.000 272.640 ;
    END
  END wbs_dat_o[17]
  PIN wbs_dat_o[18]
    DIRECTION OUTPUT TRISTATE ;
    USE SIGNAL ;
    ANTENNADIFFAREA 0.445500 ;
    PORT
      LAYER met2 ;
        RECT 589.350 0.000 589.630 4.000 ;
    END
  END wbs_dat_o[18]
  PIN wbs_dat_o[19]
    DIRECTION OUTPUT TRISTATE ;
    USE SIGNAL ;
    ANTENNADIFFAREA 0.445500 ;
    PORT
      LAYER met2 ;
        RECT 0.090 0.000 0.370 4.000 ;
    END
  END wbs_dat_o[19]
  PIN wbs_dat_o[1]
    DIRECTION OUTPUT TRISTATE ;
    USE SIGNAL ;
    ANTENNADIFFAREA 0.445500 ;
    PORT
      LAYER met2 ;
        RECT 692.390 0.000 692.670 4.000 ;
    END
  END wbs_dat_o[1]
  PIN wbs_dat_o[20]
    DIRECTION OUTPUT TRISTATE ;
    USE SIGNAL ;
    ANTENNADIFFAREA 0.445500 ;
    PORT
      LAYER met3 ;
        RECT 0.000 421.640 4.000 422.240 ;
    END
  END wbs_dat_o[20]
  PIN wbs_dat_o[21]
    DIRECTION OUTPUT TRISTATE ;
    USE SIGNAL ;
    ANTENNADIFFAREA 0.445500 ;
    PORT
      LAYER met3 ;
        RECT 0.000 788.840 4.000 789.440 ;
    END
  END wbs_dat_o[21]
  PIN wbs_dat_o[22]
    DIRECTION OUTPUT TRISTATE ;
    USE SIGNAL ;
    ANTENNADIFFAREA 0.445500 ;
    PORT
      LAYER met2 ;
        RECT 257.690 896.000 257.970 900.000 ;
    END
  END wbs_dat_o[22]
  PIN wbs_dat_o[23]
    DIRECTION OUTPUT TRISTATE ;
    USE SIGNAL ;
    ANTENNADIFFAREA 0.445500 ;
    PORT
      LAYER met3 ;
        RECT 0.000 289.040 4.000 289.640 ;
    END
  END wbs_dat_o[23]
  PIN wbs_dat_o[24]
    DIRECTION OUTPUT TRISTATE ;
    USE SIGNAL ;
    ANTENNADIFFAREA 0.445500 ;
    PORT
      LAYER met2 ;
        RECT 180.410 0.000 180.690 4.000 ;
    END
  END wbs_dat_o[24]
  PIN wbs_dat_o[25]
    DIRECTION OUTPUT TRISTATE ;
    USE SIGNAL ;
    ANTENNADIFFAREA 0.445500 ;
    PORT
      LAYER met2 ;
        RECT 61.270 0.000 61.550 4.000 ;
    END
  END wbs_dat_o[25]
  PIN wbs_dat_o[26]
    DIRECTION OUTPUT TRISTATE ;
    USE SIGNAL ;
    ANTENNADIFFAREA 0.445500 ;
    PORT
      LAYER met2 ;
        RECT 470.210 896.000 470.490 900.000 ;
    END
  END wbs_dat_o[26]
  PIN wbs_dat_o[27]
    DIRECTION OUTPUT TRISTATE ;
    USE SIGNAL ;
    ANTENNADIFFAREA 0.445500 ;
    PORT
      LAYER met2 ;
        RECT 273.790 896.000 274.070 900.000 ;
    END
  END wbs_dat_o[27]
  PIN wbs_dat_o[28]
    DIRECTION OUTPUT TRISTATE ;
    USE SIGNAL ;
    ANTENNADIFFAREA 0.445500 ;
    PORT
      LAYER met2 ;
        RECT 479.870 0.000 480.150 4.000 ;
    END
  END wbs_dat_o[28]
  PIN wbs_dat_o[29]
    DIRECTION OUTPUT TRISTATE ;
    USE SIGNAL ;
    ANTENNADIFFAREA 0.445500 ;
    PORT
      LAYER met2 ;
        RECT 627.990 896.000 628.270 900.000 ;
    END
  END wbs_dat_o[29]
  PIN wbs_dat_o[2]
    DIRECTION OUTPUT TRISTATE ;
    USE SIGNAL ;
    ANTENNADIFFAREA 0.445500 ;
    PORT
      LAYER met3 ;
        RECT 896.000 238.040 900.000 238.640 ;
    END
  END wbs_dat_o[2]
  PIN wbs_dat_o[30]
    DIRECTION OUTPUT TRISTATE ;
    USE SIGNAL ;
    ANTENNADIFFAREA 0.445500 ;
    PORT
      LAYER met3 ;
        RECT 0.000 598.440 4.000 599.040 ;
    END
  END wbs_dat_o[30]
  PIN wbs_dat_o[31]
    DIRECTION OUTPUT TRISTATE ;
    USE SIGNAL ;
    ANTENNADIFFAREA 0.445500 ;
    PORT
      LAYER met3 ;
        RECT 896.000 693.640 900.000 694.240 ;
    END
  END wbs_dat_o[31]
  PIN wbs_dat_o[3]
    DIRECTION OUTPUT TRISTATE ;
    USE SIGNAL ;
    ANTENNADIFFAREA 0.445500 ;
    PORT
      LAYER met2 ;
        RECT 196.510 0.000 196.790 4.000 ;
    END
  END wbs_dat_o[3]
  PIN wbs_dat_o[4]
    DIRECTION OUTPUT TRISTATE ;
    USE SIGNAL ;
    ANTENNADIFFAREA 0.445500 ;
    PORT
      LAYER met2 ;
        RECT 338.190 0.000 338.470 4.000 ;
    END
  END wbs_dat_o[4]
  PIN wbs_dat_o[5]
    DIRECTION OUTPUT TRISTATE ;
    USE SIGNAL ;
    ANTENNADIFFAREA 0.445500 ;
    PORT
      LAYER met2 ;
        RECT 528.170 0.000 528.450 4.000 ;
    END
  END wbs_dat_o[5]
  PIN wbs_dat_o[6]
    DIRECTION OUTPUT TRISTATE ;
    USE SIGNAL ;
    ANTENNADIFFAREA 0.445500 ;
    PORT
      LAYER met3 ;
        RECT 896.000 663.040 900.000 663.640 ;
    END
  END wbs_dat_o[6]
  PIN wbs_dat_o[7]
    DIRECTION OUTPUT TRISTATE ;
    USE SIGNAL ;
    ANTENNADIFFAREA 0.445500 ;
    PORT
      LAYER met2 ;
        RECT 534.610 0.000 534.890 4.000 ;
    END
  END wbs_dat_o[7]
  PIN wbs_dat_o[8]
    DIRECTION OUTPUT TRISTATE ;
    USE SIGNAL ;
    ANTENNADIFFAREA 0.445500 ;
    PORT
      LAYER met2 ;
        RECT 595.790 896.000 596.070 900.000 ;
    END
  END wbs_dat_o[8]
  PIN wbs_dat_o[9]
    DIRECTION OUTPUT TRISTATE ;
    USE SIGNAL ;
    ANTENNADIFFAREA 0.445500 ;
    PORT
      LAYER met2 ;
        RECT 589.350 896.000 589.630 900.000 ;
    END
  END wbs_dat_o[9]
  PIN wbs_sel_i[0]
    DIRECTION INPUT ;
    USE SIGNAL ;
    PORT
      LAYER met3 ;
        RECT 0.000 846.640 4.000 847.240 ;
    END
  END wbs_sel_i[0]
  PIN wbs_sel_i[1]
    DIRECTION INPUT ;
    USE SIGNAL ;
    PORT
      LAYER met2 ;
        RECT 116.010 896.000 116.290 900.000 ;
    END
  END wbs_sel_i[1]
  PIN wbs_sel_i[2]
    DIRECTION INPUT ;
    USE SIGNAL ;
    PORT
      LAYER met2 ;
        RECT 637.650 0.000 637.930 4.000 ;
    END
  END wbs_sel_i[2]
  PIN wbs_sel_i[3]
    DIRECTION INPUT ;
    USE SIGNAL ;
    PORT
      LAYER met3 ;
        RECT 0.000 197.240 4.000 197.840 ;
    END
  END wbs_sel_i[3]
  PIN wbs_stb_i
    DIRECTION INPUT ;
    USE SIGNAL ;
    ANTENNAGATEAREA 0.495000 ;
    PORT
      LAYER met3 ;
        RECT 0.000 765.040 4.000 765.640 ;
    END
  END wbs_stb_i
  PIN wbs_we_i
    DIRECTION INPUT ;
    USE SIGNAL ;
    ANTENNAGATEAREA 0.159000 ;
    PORT
      LAYER met3 ;
        RECT 896.000 428.440 900.000 429.040 ;
    END
  END wbs_we_i
  OBS
      LAYER li1 ;
        RECT 5.520 10.795 894.240 886.805 ;
      LAYER met1 ;
        RECT 0.070 9.900 894.630 886.960 ;
      LAYER met2 ;
        RECT 0.100 895.720 3.030 896.650 ;
        RECT 3.870 895.720 12.690 896.650 ;
        RECT 13.530 895.720 19.130 896.650 ;
        RECT 19.970 895.720 28.790 896.650 ;
        RECT 29.630 895.720 35.230 896.650 ;
        RECT 36.070 895.720 44.890 896.650 ;
        RECT 45.730 895.720 51.330 896.650 ;
        RECT 52.170 895.720 60.990 896.650 ;
        RECT 61.830 895.720 67.430 896.650 ;
        RECT 68.270 895.720 77.090 896.650 ;
        RECT 77.930 895.720 83.530 896.650 ;
        RECT 84.370 895.720 89.970 896.650 ;
        RECT 90.810 895.720 99.630 896.650 ;
        RECT 100.470 895.720 106.070 896.650 ;
        RECT 106.910 895.720 115.730 896.650 ;
        RECT 116.570 895.720 122.170 896.650 ;
        RECT 123.010 895.720 131.830 896.650 ;
        RECT 132.670 895.720 138.270 896.650 ;
        RECT 139.110 895.720 147.930 896.650 ;
        RECT 148.770 895.720 154.370 896.650 ;
        RECT 155.210 895.720 160.810 896.650 ;
        RECT 161.650 895.720 170.470 896.650 ;
        RECT 171.310 895.720 176.910 896.650 ;
        RECT 177.750 895.720 186.570 896.650 ;
        RECT 187.410 895.720 193.010 896.650 ;
        RECT 193.850 895.720 202.670 896.650 ;
        RECT 203.510 895.720 209.110 896.650 ;
        RECT 209.950 895.720 218.770 896.650 ;
        RECT 219.610 895.720 225.210 896.650 ;
        RECT 226.050 895.720 234.870 896.650 ;
        RECT 235.710 895.720 241.310 896.650 ;
        RECT 242.150 895.720 247.750 896.650 ;
        RECT 248.590 895.720 257.410 896.650 ;
        RECT 258.250 895.720 263.850 896.650 ;
        RECT 264.690 895.720 273.510 896.650 ;
        RECT 274.350 895.720 279.950 896.650 ;
        RECT 280.790 895.720 289.610 896.650 ;
        RECT 290.450 895.720 296.050 896.650 ;
        RECT 296.890 895.720 305.710 896.650 ;
        RECT 306.550 895.720 312.150 896.650 ;
        RECT 312.990 895.720 318.590 896.650 ;
        RECT 319.430 895.720 328.250 896.650 ;
        RECT 329.090 895.720 334.690 896.650 ;
        RECT 335.530 895.720 344.350 896.650 ;
        RECT 345.190 895.720 350.790 896.650 ;
        RECT 351.630 895.720 360.450 896.650 ;
        RECT 361.290 895.720 366.890 896.650 ;
        RECT 367.730 895.720 376.550 896.650 ;
        RECT 377.390 895.720 382.990 896.650 ;
        RECT 383.830 895.720 392.650 896.650 ;
        RECT 393.490 895.720 399.090 896.650 ;
        RECT 399.930 895.720 405.530 896.650 ;
        RECT 406.370 895.720 415.190 896.650 ;
        RECT 416.030 895.720 421.630 896.650 ;
        RECT 422.470 895.720 431.290 896.650 ;
        RECT 432.130 895.720 437.730 896.650 ;
        RECT 438.570 895.720 447.390 896.650 ;
        RECT 448.230 895.720 453.830 896.650 ;
        RECT 454.670 895.720 463.490 896.650 ;
        RECT 464.330 895.720 469.930 896.650 ;
        RECT 470.770 895.720 476.370 896.650 ;
        RECT 477.210 895.720 486.030 896.650 ;
        RECT 486.870 895.720 492.470 896.650 ;
        RECT 493.310 895.720 502.130 896.650 ;
        RECT 502.970 895.720 508.570 896.650 ;
        RECT 509.410 895.720 518.230 896.650 ;
        RECT 519.070 895.720 524.670 896.650 ;
        RECT 525.510 895.720 534.330 896.650 ;
        RECT 535.170 895.720 540.770 896.650 ;
        RECT 541.610 895.720 547.210 896.650 ;
        RECT 548.050 895.720 556.870 896.650 ;
        RECT 557.710 895.720 563.310 896.650 ;
        RECT 564.150 895.720 572.970 896.650 ;
        RECT 573.810 895.720 579.410 896.650 ;
        RECT 580.250 895.720 589.070 896.650 ;
        RECT 589.910 895.720 595.510 896.650 ;
        RECT 596.350 895.720 605.170 896.650 ;
        RECT 606.010 895.720 611.610 896.650 ;
        RECT 612.450 895.720 621.270 896.650 ;
        RECT 622.110 895.720 627.710 896.650 ;
        RECT 628.550 895.720 634.150 896.650 ;
        RECT 634.990 895.720 643.810 896.650 ;
        RECT 644.650 895.720 650.250 896.650 ;
        RECT 651.090 895.720 659.910 896.650 ;
        RECT 660.750 895.720 666.350 896.650 ;
        RECT 667.190 895.720 676.010 896.650 ;
        RECT 676.850 895.720 682.450 896.650 ;
        RECT 683.290 895.720 692.110 896.650 ;
        RECT 692.950 895.720 698.550 896.650 ;
        RECT 699.390 895.720 704.990 896.650 ;
        RECT 705.830 895.720 714.650 896.650 ;
        RECT 715.490 895.720 721.090 896.650 ;
        RECT 721.930 895.720 730.750 896.650 ;
        RECT 731.590 895.720 737.190 896.650 ;
        RECT 738.030 895.720 746.850 896.650 ;
        RECT 747.690 895.720 753.290 896.650 ;
        RECT 754.130 895.720 762.950 896.650 ;
        RECT 763.790 895.720 769.390 896.650 ;
        RECT 770.230 895.720 779.050 896.650 ;
        RECT 779.890 895.720 785.490 896.650 ;
        RECT 786.330 895.720 791.930 896.650 ;
        RECT 792.770 895.720 801.590 896.650 ;
        RECT 802.430 895.720 808.030 896.650 ;
        RECT 808.870 895.720 817.690 896.650 ;
        RECT 818.530 895.720 824.130 896.650 ;
        RECT 824.970 895.720 833.790 896.650 ;
        RECT 834.630 895.720 840.230 896.650 ;
        RECT 841.070 895.720 849.890 896.650 ;
        RECT 850.730 895.720 856.330 896.650 ;
        RECT 857.170 895.720 862.770 896.650 ;
        RECT 863.610 895.720 872.430 896.650 ;
        RECT 873.270 895.720 878.870 896.650 ;
        RECT 879.710 895.720 888.530 896.650 ;
        RECT 889.370 895.720 894.610 896.650 ;
        RECT 0.100 4.280 894.610 895.720 ;
        RECT 0.650 3.670 6.250 4.280 ;
        RECT 7.090 3.670 12.690 4.280 ;
        RECT 13.530 3.670 22.350 4.280 ;
        RECT 23.190 3.670 28.790 4.280 ;
        RECT 29.630 3.670 38.450 4.280 ;
        RECT 39.290 3.670 44.890 4.280 ;
        RECT 45.730 3.670 54.550 4.280 ;
        RECT 55.390 3.670 60.990 4.280 ;
        RECT 61.830 3.670 70.650 4.280 ;
        RECT 71.490 3.670 77.090 4.280 ;
        RECT 77.930 3.670 83.530 4.280 ;
        RECT 84.370 3.670 93.190 4.280 ;
        RECT 94.030 3.670 99.630 4.280 ;
        RECT 100.470 3.670 109.290 4.280 ;
        RECT 110.130 3.670 115.730 4.280 ;
        RECT 116.570 3.670 125.390 4.280 ;
        RECT 126.230 3.670 131.830 4.280 ;
        RECT 132.670 3.670 141.490 4.280 ;
        RECT 142.330 3.670 147.930 4.280 ;
        RECT 148.770 3.670 154.370 4.280 ;
        RECT 155.210 3.670 164.030 4.280 ;
        RECT 164.870 3.670 170.470 4.280 ;
        RECT 171.310 3.670 180.130 4.280 ;
        RECT 180.970 3.670 186.570 4.280 ;
        RECT 187.410 3.670 196.230 4.280 ;
        RECT 197.070 3.670 202.670 4.280 ;
        RECT 203.510 3.670 212.330 4.280 ;
        RECT 213.170 3.670 218.770 4.280 ;
        RECT 219.610 3.670 228.430 4.280 ;
        RECT 229.270 3.670 234.870 4.280 ;
        RECT 235.710 3.670 241.310 4.280 ;
        RECT 242.150 3.670 250.970 4.280 ;
        RECT 251.810 3.670 257.410 4.280 ;
        RECT 258.250 3.670 267.070 4.280 ;
        RECT 267.910 3.670 273.510 4.280 ;
        RECT 274.350 3.670 283.170 4.280 ;
        RECT 284.010 3.670 289.610 4.280 ;
        RECT 290.450 3.670 299.270 4.280 ;
        RECT 300.110 3.670 305.710 4.280 ;
        RECT 306.550 3.670 312.150 4.280 ;
        RECT 312.990 3.670 321.810 4.280 ;
        RECT 322.650 3.670 328.250 4.280 ;
        RECT 329.090 3.670 337.910 4.280 ;
        RECT 338.750 3.670 344.350 4.280 ;
        RECT 345.190 3.670 354.010 4.280 ;
        RECT 354.850 3.670 360.450 4.280 ;
        RECT 361.290 3.670 370.110 4.280 ;
        RECT 370.950 3.670 376.550 4.280 ;
        RECT 377.390 3.670 386.210 4.280 ;
        RECT 387.050 3.670 392.650 4.280 ;
        RECT 393.490 3.670 399.090 4.280 ;
        RECT 399.930 3.670 408.750 4.280 ;
        RECT 409.590 3.670 415.190 4.280 ;
        RECT 416.030 3.670 424.850 4.280 ;
        RECT 425.690 3.670 431.290 4.280 ;
        RECT 432.130 3.670 440.950 4.280 ;
        RECT 441.790 3.670 447.390 4.280 ;
        RECT 448.230 3.670 457.050 4.280 ;
        RECT 457.890 3.670 463.490 4.280 ;
        RECT 464.330 3.670 469.930 4.280 ;
        RECT 470.770 3.670 479.590 4.280 ;
        RECT 480.430 3.670 486.030 4.280 ;
        RECT 486.870 3.670 495.690 4.280 ;
        RECT 496.530 3.670 502.130 4.280 ;
        RECT 502.970 3.670 511.790 4.280 ;
        RECT 512.630 3.670 518.230 4.280 ;
        RECT 519.070 3.670 527.890 4.280 ;
        RECT 528.730 3.670 534.330 4.280 ;
        RECT 535.170 3.670 543.990 4.280 ;
        RECT 544.830 3.670 550.430 4.280 ;
        RECT 551.270 3.670 556.870 4.280 ;
        RECT 557.710 3.670 566.530 4.280 ;
        RECT 567.370 3.670 572.970 4.280 ;
        RECT 573.810 3.670 582.630 4.280 ;
        RECT 583.470 3.670 589.070 4.280 ;
        RECT 589.910 3.670 598.730 4.280 ;
        RECT 599.570 3.670 605.170 4.280 ;
        RECT 606.010 3.670 614.830 4.280 ;
        RECT 615.670 3.670 621.270 4.280 ;
        RECT 622.110 3.670 627.710 4.280 ;
        RECT 628.550 3.670 637.370 4.280 ;
        RECT 638.210 3.670 643.810 4.280 ;
        RECT 644.650 3.670 653.470 4.280 ;
        RECT 654.310 3.670 659.910 4.280 ;
        RECT 660.750 3.670 669.570 4.280 ;
        RECT 670.410 3.670 676.010 4.280 ;
        RECT 676.850 3.670 685.670 4.280 ;
        RECT 686.510 3.670 692.110 4.280 ;
        RECT 692.950 3.670 701.770 4.280 ;
        RECT 702.610 3.670 708.210 4.280 ;
        RECT 709.050 3.670 714.650 4.280 ;
        RECT 715.490 3.670 724.310 4.280 ;
        RECT 725.150 3.670 730.750 4.280 ;
        RECT 731.590 3.670 740.410 4.280 ;
        RECT 741.250 3.670 746.850 4.280 ;
        RECT 747.690 3.670 756.510 4.280 ;
        RECT 757.350 3.670 762.950 4.280 ;
        RECT 763.790 3.670 772.610 4.280 ;
        RECT 773.450 3.670 779.050 4.280 ;
        RECT 779.890 3.670 785.490 4.280 ;
        RECT 786.330 3.670 795.150 4.280 ;
        RECT 795.990 3.670 801.590 4.280 ;
        RECT 802.430 3.670 811.250 4.280 ;
        RECT 812.090 3.670 817.690 4.280 ;
        RECT 818.530 3.670 827.350 4.280 ;
        RECT 828.190 3.670 833.790 4.280 ;
        RECT 834.630 3.670 843.450 4.280 ;
        RECT 844.290 3.670 849.890 4.280 ;
        RECT 850.730 3.670 856.330 4.280 ;
        RECT 857.170 3.670 865.990 4.280 ;
        RECT 866.830 3.670 872.430 4.280 ;
        RECT 873.270 3.670 882.090 4.280 ;
        RECT 882.930 3.670 888.530 4.280 ;
        RECT 889.370 3.670 894.610 4.280 ;
      LAYER met3 ;
        RECT 4.000 893.840 895.600 894.705 ;
        RECT 4.000 891.840 896.000 893.840 ;
        RECT 4.400 890.440 896.000 891.840 ;
        RECT 4.000 888.440 896.000 890.440 ;
        RECT 4.000 887.040 895.600 888.440 ;
        RECT 4.000 881.640 896.000 887.040 ;
        RECT 4.400 880.240 896.000 881.640 ;
        RECT 4.000 878.240 896.000 880.240 ;
        RECT 4.000 876.840 895.600 878.240 ;
        RECT 4.000 874.840 896.000 876.840 ;
        RECT 4.400 873.440 896.000 874.840 ;
        RECT 4.000 871.440 896.000 873.440 ;
        RECT 4.000 870.040 895.600 871.440 ;
        RECT 4.000 864.640 896.000 870.040 ;
        RECT 4.400 863.240 896.000 864.640 ;
        RECT 4.000 861.240 896.000 863.240 ;
        RECT 4.000 859.840 895.600 861.240 ;
        RECT 4.000 857.840 896.000 859.840 ;
        RECT 4.400 856.440 896.000 857.840 ;
        RECT 4.000 854.440 896.000 856.440 ;
        RECT 4.000 853.040 895.600 854.440 ;
        RECT 4.000 847.640 896.000 853.040 ;
        RECT 4.400 846.240 895.600 847.640 ;
        RECT 4.000 840.840 896.000 846.240 ;
        RECT 4.400 839.440 896.000 840.840 ;
        RECT 4.000 837.440 896.000 839.440 ;
        RECT 4.000 836.040 895.600 837.440 ;
        RECT 4.000 830.640 896.000 836.040 ;
        RECT 4.400 829.240 895.600 830.640 ;
        RECT 4.000 823.840 896.000 829.240 ;
        RECT 4.400 822.440 896.000 823.840 ;
        RECT 4.000 820.440 896.000 822.440 ;
        RECT 4.000 819.040 895.600 820.440 ;
        RECT 4.000 817.040 896.000 819.040 ;
        RECT 4.400 815.640 896.000 817.040 ;
        RECT 4.000 813.640 896.000 815.640 ;
        RECT 4.000 812.240 895.600 813.640 ;
        RECT 4.000 806.840 896.000 812.240 ;
        RECT 4.400 805.440 896.000 806.840 ;
        RECT 4.000 803.440 896.000 805.440 ;
        RECT 4.000 802.040 895.600 803.440 ;
        RECT 4.000 800.040 896.000 802.040 ;
        RECT 4.400 798.640 896.000 800.040 ;
        RECT 4.000 796.640 896.000 798.640 ;
        RECT 4.000 795.240 895.600 796.640 ;
        RECT 4.000 789.840 896.000 795.240 ;
        RECT 4.400 788.440 896.000 789.840 ;
        RECT 4.000 786.440 896.000 788.440 ;
        RECT 4.000 785.040 895.600 786.440 ;
        RECT 4.000 783.040 896.000 785.040 ;
        RECT 4.400 781.640 896.000 783.040 ;
        RECT 4.000 779.640 896.000 781.640 ;
        RECT 4.000 778.240 895.600 779.640 ;
        RECT 4.000 772.840 896.000 778.240 ;
        RECT 4.400 771.440 895.600 772.840 ;
        RECT 4.000 766.040 896.000 771.440 ;
        RECT 4.400 764.640 896.000 766.040 ;
        RECT 4.000 762.640 896.000 764.640 ;
        RECT 4.000 761.240 895.600 762.640 ;
        RECT 4.000 755.840 896.000 761.240 ;
        RECT 4.400 754.440 895.600 755.840 ;
        RECT 4.000 749.040 896.000 754.440 ;
        RECT 4.400 747.640 896.000 749.040 ;
        RECT 4.000 745.640 896.000 747.640 ;
        RECT 4.000 744.240 895.600 745.640 ;
        RECT 4.000 738.840 896.000 744.240 ;
        RECT 4.400 737.440 895.600 738.840 ;
        RECT 4.000 732.040 896.000 737.440 ;
        RECT 4.400 730.640 896.000 732.040 ;
        RECT 4.000 728.640 896.000 730.640 ;
        RECT 4.000 727.240 895.600 728.640 ;
        RECT 4.000 725.240 896.000 727.240 ;
        RECT 4.400 723.840 896.000 725.240 ;
        RECT 4.000 721.840 896.000 723.840 ;
        RECT 4.000 720.440 895.600 721.840 ;
        RECT 4.000 715.040 896.000 720.440 ;
        RECT 4.400 713.640 896.000 715.040 ;
        RECT 4.000 711.640 896.000 713.640 ;
        RECT 4.000 710.240 895.600 711.640 ;
        RECT 4.000 708.240 896.000 710.240 ;
        RECT 4.400 706.840 896.000 708.240 ;
        RECT 4.000 704.840 896.000 706.840 ;
        RECT 4.000 703.440 895.600 704.840 ;
        RECT 4.000 698.040 896.000 703.440 ;
        RECT 4.400 696.640 896.000 698.040 ;
        RECT 4.000 694.640 896.000 696.640 ;
        RECT 4.000 693.240 895.600 694.640 ;
        RECT 4.000 691.240 896.000 693.240 ;
        RECT 4.400 689.840 896.000 691.240 ;
        RECT 4.000 687.840 896.000 689.840 ;
        RECT 4.000 686.440 895.600 687.840 ;
        RECT 4.000 681.040 896.000 686.440 ;
        RECT 4.400 679.640 895.600 681.040 ;
        RECT 4.000 674.240 896.000 679.640 ;
        RECT 4.400 672.840 896.000 674.240 ;
        RECT 4.000 670.840 896.000 672.840 ;
        RECT 4.000 669.440 895.600 670.840 ;
        RECT 4.000 664.040 896.000 669.440 ;
        RECT 4.400 662.640 895.600 664.040 ;
        RECT 4.000 657.240 896.000 662.640 ;
        RECT 4.400 655.840 896.000 657.240 ;
        RECT 4.000 653.840 896.000 655.840 ;
        RECT 4.000 652.440 895.600 653.840 ;
        RECT 4.000 650.440 896.000 652.440 ;
        RECT 4.400 649.040 896.000 650.440 ;
        RECT 4.000 647.040 896.000 649.040 ;
        RECT 4.000 645.640 895.600 647.040 ;
        RECT 4.000 640.240 896.000 645.640 ;
        RECT 4.400 638.840 896.000 640.240 ;
        RECT 4.000 636.840 896.000 638.840 ;
        RECT 4.000 635.440 895.600 636.840 ;
        RECT 4.000 633.440 896.000 635.440 ;
        RECT 4.400 632.040 896.000 633.440 ;
        RECT 4.000 630.040 896.000 632.040 ;
        RECT 4.000 628.640 895.600 630.040 ;
        RECT 4.000 623.240 896.000 628.640 ;
        RECT 4.400 621.840 896.000 623.240 ;
        RECT 4.000 619.840 896.000 621.840 ;
        RECT 4.000 618.440 895.600 619.840 ;
        RECT 4.000 616.440 896.000 618.440 ;
        RECT 4.400 615.040 896.000 616.440 ;
        RECT 4.000 613.040 896.000 615.040 ;
        RECT 4.000 611.640 895.600 613.040 ;
        RECT 4.000 606.240 896.000 611.640 ;
        RECT 4.400 604.840 895.600 606.240 ;
        RECT 4.000 599.440 896.000 604.840 ;
        RECT 4.400 598.040 896.000 599.440 ;
        RECT 4.000 596.040 896.000 598.040 ;
        RECT 4.000 594.640 895.600 596.040 ;
        RECT 4.000 589.240 896.000 594.640 ;
        RECT 4.400 587.840 895.600 589.240 ;
        RECT 4.000 582.440 896.000 587.840 ;
        RECT 4.400 581.040 896.000 582.440 ;
        RECT 4.000 579.040 896.000 581.040 ;
        RECT 4.000 577.640 895.600 579.040 ;
        RECT 4.000 575.640 896.000 577.640 ;
        RECT 4.400 574.240 896.000 575.640 ;
        RECT 4.000 572.240 896.000 574.240 ;
        RECT 4.000 570.840 895.600 572.240 ;
        RECT 4.000 565.440 896.000 570.840 ;
        RECT 4.400 564.040 896.000 565.440 ;
        RECT 4.000 562.040 896.000 564.040 ;
        RECT 4.000 560.640 895.600 562.040 ;
        RECT 4.000 558.640 896.000 560.640 ;
        RECT 4.400 557.240 896.000 558.640 ;
        RECT 4.000 555.240 896.000 557.240 ;
        RECT 4.000 553.840 895.600 555.240 ;
        RECT 4.000 548.440 896.000 553.840 ;
        RECT 4.400 547.040 896.000 548.440 ;
        RECT 4.000 545.040 896.000 547.040 ;
        RECT 4.000 543.640 895.600 545.040 ;
        RECT 4.000 541.640 896.000 543.640 ;
        RECT 4.400 540.240 896.000 541.640 ;
        RECT 4.000 538.240 896.000 540.240 ;
        RECT 4.000 536.840 895.600 538.240 ;
        RECT 4.000 531.440 896.000 536.840 ;
        RECT 4.400 530.040 895.600 531.440 ;
        RECT 4.000 524.640 896.000 530.040 ;
        RECT 4.400 523.240 896.000 524.640 ;
        RECT 4.000 521.240 896.000 523.240 ;
        RECT 4.000 519.840 895.600 521.240 ;
        RECT 4.000 514.440 896.000 519.840 ;
        RECT 4.400 513.040 895.600 514.440 ;
        RECT 4.000 507.640 896.000 513.040 ;
        RECT 4.400 506.240 896.000 507.640 ;
        RECT 4.000 504.240 896.000 506.240 ;
        RECT 4.000 502.840 895.600 504.240 ;
        RECT 4.000 497.440 896.000 502.840 ;
        RECT 4.400 496.040 895.600 497.440 ;
        RECT 4.000 490.640 896.000 496.040 ;
        RECT 4.400 489.240 896.000 490.640 ;
        RECT 4.000 487.240 896.000 489.240 ;
        RECT 4.000 485.840 895.600 487.240 ;
        RECT 4.000 483.840 896.000 485.840 ;
        RECT 4.400 482.440 896.000 483.840 ;
        RECT 4.000 480.440 896.000 482.440 ;
        RECT 4.000 479.040 895.600 480.440 ;
        RECT 4.000 473.640 896.000 479.040 ;
        RECT 4.400 472.240 896.000 473.640 ;
        RECT 4.000 470.240 896.000 472.240 ;
        RECT 4.000 468.840 895.600 470.240 ;
        RECT 4.000 466.840 896.000 468.840 ;
        RECT 4.400 465.440 896.000 466.840 ;
        RECT 4.000 463.440 896.000 465.440 ;
        RECT 4.000 462.040 895.600 463.440 ;
        RECT 4.000 456.640 896.000 462.040 ;
        RECT 4.400 455.240 896.000 456.640 ;
        RECT 4.000 453.240 896.000 455.240 ;
        RECT 4.000 451.840 895.600 453.240 ;
        RECT 4.000 449.840 896.000 451.840 ;
        RECT 4.400 448.440 896.000 449.840 ;
        RECT 4.000 446.440 896.000 448.440 ;
        RECT 4.000 445.040 895.600 446.440 ;
        RECT 4.000 439.640 896.000 445.040 ;
        RECT 4.400 438.240 895.600 439.640 ;
        RECT 4.000 432.840 896.000 438.240 ;
        RECT 4.400 431.440 896.000 432.840 ;
        RECT 4.000 429.440 896.000 431.440 ;
        RECT 4.000 428.040 895.600 429.440 ;
        RECT 4.000 422.640 896.000 428.040 ;
        RECT 4.400 421.240 895.600 422.640 ;
        RECT 4.000 415.840 896.000 421.240 ;
        RECT 4.400 414.440 896.000 415.840 ;
        RECT 4.000 412.440 896.000 414.440 ;
        RECT 4.000 411.040 895.600 412.440 ;
        RECT 4.000 409.040 896.000 411.040 ;
        RECT 4.400 407.640 896.000 409.040 ;
        RECT 4.000 405.640 896.000 407.640 ;
        RECT 4.000 404.240 895.600 405.640 ;
        RECT 4.000 398.840 896.000 404.240 ;
        RECT 4.400 397.440 896.000 398.840 ;
        RECT 4.000 395.440 896.000 397.440 ;
        RECT 4.000 394.040 895.600 395.440 ;
        RECT 4.000 392.040 896.000 394.040 ;
        RECT 4.400 390.640 896.000 392.040 ;
        RECT 4.000 388.640 896.000 390.640 ;
        RECT 4.000 387.240 895.600 388.640 ;
        RECT 4.000 381.840 896.000 387.240 ;
        RECT 4.400 380.440 896.000 381.840 ;
        RECT 4.000 378.440 896.000 380.440 ;
        RECT 4.000 377.040 895.600 378.440 ;
        RECT 4.000 375.040 896.000 377.040 ;
        RECT 4.400 373.640 896.000 375.040 ;
        RECT 4.000 371.640 896.000 373.640 ;
        RECT 4.000 370.240 895.600 371.640 ;
        RECT 4.000 364.840 896.000 370.240 ;
        RECT 4.400 363.440 895.600 364.840 ;
        RECT 4.000 358.040 896.000 363.440 ;
        RECT 4.400 356.640 896.000 358.040 ;
        RECT 4.000 354.640 896.000 356.640 ;
        RECT 4.000 353.240 895.600 354.640 ;
        RECT 4.000 347.840 896.000 353.240 ;
        RECT 4.400 346.440 895.600 347.840 ;
        RECT 4.000 341.040 896.000 346.440 ;
        RECT 4.400 339.640 896.000 341.040 ;
        RECT 4.000 337.640 896.000 339.640 ;
        RECT 4.000 336.240 895.600 337.640 ;
        RECT 4.000 330.840 896.000 336.240 ;
        RECT 4.400 329.440 895.600 330.840 ;
        RECT 4.000 324.040 896.000 329.440 ;
        RECT 4.400 322.640 896.000 324.040 ;
        RECT 4.000 320.640 896.000 322.640 ;
        RECT 4.000 319.240 895.600 320.640 ;
        RECT 4.000 317.240 896.000 319.240 ;
        RECT 4.400 315.840 896.000 317.240 ;
        RECT 4.000 313.840 896.000 315.840 ;
        RECT 4.000 312.440 895.600 313.840 ;
        RECT 4.000 307.040 896.000 312.440 ;
        RECT 4.400 305.640 896.000 307.040 ;
        RECT 4.000 303.640 896.000 305.640 ;
        RECT 4.000 302.240 895.600 303.640 ;
        RECT 4.000 300.240 896.000 302.240 ;
        RECT 4.400 298.840 896.000 300.240 ;
        RECT 4.000 296.840 896.000 298.840 ;
        RECT 4.000 295.440 895.600 296.840 ;
        RECT 4.000 290.040 896.000 295.440 ;
        RECT 4.400 288.640 896.000 290.040 ;
        RECT 4.000 286.640 896.000 288.640 ;
        RECT 4.000 285.240 895.600 286.640 ;
        RECT 4.000 283.240 896.000 285.240 ;
        RECT 4.400 281.840 896.000 283.240 ;
        RECT 4.000 279.840 896.000 281.840 ;
        RECT 4.000 278.440 895.600 279.840 ;
        RECT 4.000 273.040 896.000 278.440 ;
        RECT 4.400 271.640 895.600 273.040 ;
        RECT 4.000 266.240 896.000 271.640 ;
        RECT 4.400 264.840 896.000 266.240 ;
        RECT 4.000 262.840 896.000 264.840 ;
        RECT 4.000 261.440 895.600 262.840 ;
        RECT 4.000 256.040 896.000 261.440 ;
        RECT 4.400 254.640 895.600 256.040 ;
        RECT 4.000 249.240 896.000 254.640 ;
        RECT 4.400 247.840 896.000 249.240 ;
        RECT 4.000 245.840 896.000 247.840 ;
        RECT 4.000 244.440 895.600 245.840 ;
        RECT 4.000 242.440 896.000 244.440 ;
        RECT 4.400 241.040 896.000 242.440 ;
        RECT 4.000 239.040 896.000 241.040 ;
        RECT 4.000 237.640 895.600 239.040 ;
        RECT 4.000 232.240 896.000 237.640 ;
        RECT 4.400 230.840 896.000 232.240 ;
        RECT 4.000 228.840 896.000 230.840 ;
        RECT 4.000 227.440 895.600 228.840 ;
        RECT 4.000 225.440 896.000 227.440 ;
        RECT 4.400 224.040 896.000 225.440 ;
        RECT 4.000 222.040 896.000 224.040 ;
        RECT 4.000 220.640 895.600 222.040 ;
        RECT 4.000 215.240 896.000 220.640 ;
        RECT 4.400 213.840 896.000 215.240 ;
        RECT 4.000 211.840 896.000 213.840 ;
        RECT 4.000 210.440 895.600 211.840 ;
        RECT 4.000 208.440 896.000 210.440 ;
        RECT 4.400 207.040 896.000 208.440 ;
        RECT 4.000 205.040 896.000 207.040 ;
        RECT 4.000 203.640 895.600 205.040 ;
        RECT 4.000 198.240 896.000 203.640 ;
        RECT 4.400 196.840 895.600 198.240 ;
        RECT 4.000 191.440 896.000 196.840 ;
        RECT 4.400 190.040 896.000 191.440 ;
        RECT 4.000 188.040 896.000 190.040 ;
        RECT 4.000 186.640 895.600 188.040 ;
        RECT 4.000 181.240 896.000 186.640 ;
        RECT 4.400 179.840 895.600 181.240 ;
        RECT 4.000 174.440 896.000 179.840 ;
        RECT 4.400 173.040 896.000 174.440 ;
        RECT 4.000 171.040 896.000 173.040 ;
        RECT 4.000 169.640 895.600 171.040 ;
        RECT 4.000 164.240 896.000 169.640 ;
        RECT 4.400 162.840 895.600 164.240 ;
        RECT 4.000 157.440 896.000 162.840 ;
        RECT 4.400 156.040 896.000 157.440 ;
        RECT 4.000 154.040 896.000 156.040 ;
        RECT 4.000 152.640 895.600 154.040 ;
        RECT 4.000 150.640 896.000 152.640 ;
        RECT 4.400 149.240 896.000 150.640 ;
        RECT 4.000 147.240 896.000 149.240 ;
        RECT 4.000 145.840 895.600 147.240 ;
        RECT 4.000 140.440 896.000 145.840 ;
        RECT 4.400 139.040 896.000 140.440 ;
        RECT 4.000 137.040 896.000 139.040 ;
        RECT 4.000 135.640 895.600 137.040 ;
        RECT 4.000 133.640 896.000 135.640 ;
        RECT 4.400 132.240 896.000 133.640 ;
        RECT 4.000 130.240 896.000 132.240 ;
        RECT 4.000 128.840 895.600 130.240 ;
        RECT 4.000 123.440 896.000 128.840 ;
        RECT 4.400 122.040 896.000 123.440 ;
        RECT 4.000 120.040 896.000 122.040 ;
        RECT 4.000 118.640 895.600 120.040 ;
        RECT 4.000 116.640 896.000 118.640 ;
        RECT 4.400 115.240 896.000 116.640 ;
        RECT 4.000 113.240 896.000 115.240 ;
        RECT 4.000 111.840 895.600 113.240 ;
        RECT 4.000 106.440 896.000 111.840 ;
        RECT 4.400 105.040 895.600 106.440 ;
        RECT 4.000 99.640 896.000 105.040 ;
        RECT 4.400 98.240 896.000 99.640 ;
        RECT 4.000 96.240 896.000 98.240 ;
        RECT 4.000 94.840 895.600 96.240 ;
        RECT 4.000 89.440 896.000 94.840 ;
        RECT 4.400 88.040 895.600 89.440 ;
        RECT 4.000 82.640 896.000 88.040 ;
        RECT 4.400 81.240 896.000 82.640 ;
        RECT 4.000 79.240 896.000 81.240 ;
        RECT 4.000 77.840 895.600 79.240 ;
        RECT 4.000 75.840 896.000 77.840 ;
        RECT 4.400 74.440 896.000 75.840 ;
        RECT 4.000 72.440 896.000 74.440 ;
        RECT 4.000 71.040 895.600 72.440 ;
        RECT 4.000 65.640 896.000 71.040 ;
        RECT 4.400 64.240 896.000 65.640 ;
        RECT 4.000 62.240 896.000 64.240 ;
        RECT 4.000 60.840 895.600 62.240 ;
        RECT 4.000 58.840 896.000 60.840 ;
        RECT 4.400 57.440 896.000 58.840 ;
        RECT 4.000 55.440 896.000 57.440 ;
        RECT 4.000 54.040 895.600 55.440 ;
        RECT 4.000 48.640 896.000 54.040 ;
        RECT 4.400 47.240 896.000 48.640 ;
        RECT 4.000 45.240 896.000 47.240 ;
        RECT 4.000 43.840 895.600 45.240 ;
        RECT 4.000 41.840 896.000 43.840 ;
        RECT 4.400 40.440 896.000 41.840 ;
        RECT 4.000 38.440 896.000 40.440 ;
        RECT 4.000 37.040 895.600 38.440 ;
        RECT 4.000 31.640 896.000 37.040 ;
        RECT 4.400 30.240 895.600 31.640 ;
        RECT 4.000 24.840 896.000 30.240 ;
        RECT 4.400 23.440 896.000 24.840 ;
        RECT 4.000 21.440 896.000 23.440 ;
        RECT 4.000 20.040 895.600 21.440 ;
        RECT 4.000 14.640 896.000 20.040 ;
        RECT 4.400 13.240 895.600 14.640 ;
        RECT 4.000 10.715 896.000 13.240 ;
      LAYER met4 ;
        RECT 574.375 11.735 574.705 305.145 ;
  END
END TOP_digital
END LIBRARY

